VERSION 5.8 ;
BUSBITCHARS "[]" ;
DIVIDERCHAR "/" ;
UNITS
    DATABASE MICRONS 1000 ;
END UNITS

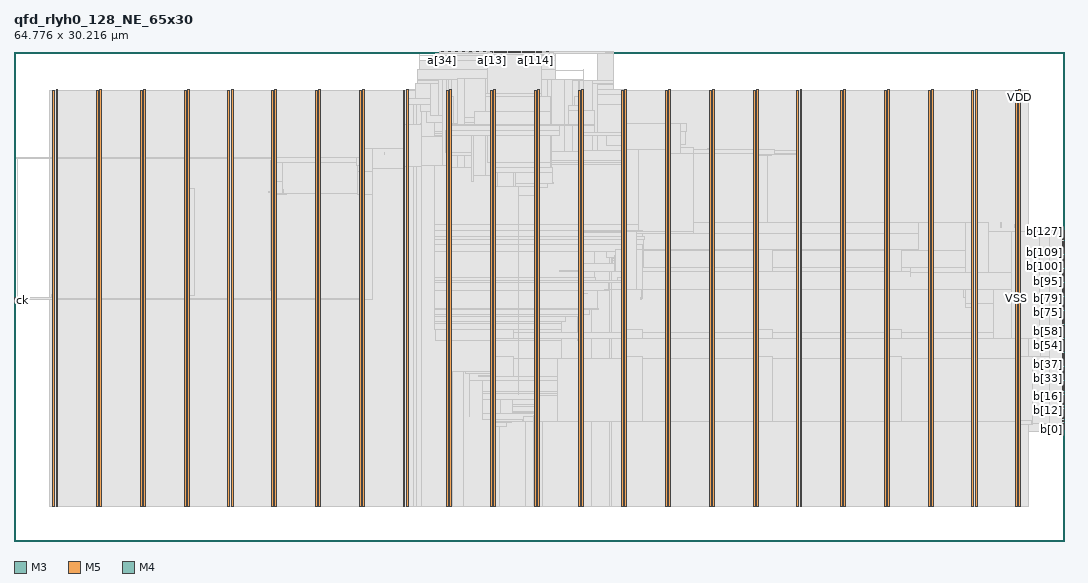
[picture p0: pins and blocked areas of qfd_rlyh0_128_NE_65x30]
MACRO qfd_rlyh0_128_NE_65x30
  FOREIGN qfd_rlyh0_128_NE_65x30 0 0 ;
  CLASS BLOCK ;
  SIZE 64.776 BY 30.216 ;
  PIN a[0]
    DIRECTION INPUT ;
    USE SIGNAL ;
    PORT
      LAYER M3 ;
        RECT  28.548 30.179 28.566 30.216 ;
    END
  END a[0]
  PIN a[100]
    DIRECTION INPUT ;
    USE SIGNAL ;
    PORT
      LAYER M3 ;
        RECT  31.14 30.179 31.158 30.216 ;
    END
  END a[100]
  PIN a[101]
    DIRECTION INPUT ;
    USE SIGNAL ;
    PORT
      LAYER M3 ;
        RECT  31.212 30.179 31.23 30.216 ;
    END
  END a[101]
  PIN a[102]
    DIRECTION INPUT ;
    USE SIGNAL ;
    PORT
      LAYER M3 ;
        RECT  31.284 30.179 31.302 30.216 ;
    END
  END a[102]
  PIN a[103]
    DIRECTION INPUT ;
    USE SIGNAL ;
    PORT
      LAYER M3 ;
        RECT  31.356 30.179 31.374 30.216 ;
    END
  END a[103]
  PIN a[104]
    DIRECTION INPUT ;
    USE SIGNAL ;
    PORT
      LAYER M3 ;
        RECT  31.428 30.179 31.446 30.216 ;
    END
  END a[104]
  PIN a[105]
    DIRECTION INPUT ;
    USE SIGNAL ;
    PORT
      LAYER M3 ;
        RECT  31.5 30.179 31.518 30.216 ;
    END
  END a[105]
  PIN a[106]
    DIRECTION INPUT ;
    USE SIGNAL ;
    PORT
      LAYER M3 ;
        RECT  31.572 30.179 31.59 30.216 ;
    END
  END a[106]
  PIN a[107]
    DIRECTION INPUT ;
    USE SIGNAL ;
    PORT
      LAYER M3 ;
        RECT  31.644 30.179 31.662 30.216 ;
    END
  END a[107]
  PIN a[108]
    DIRECTION INPUT ;
    USE SIGNAL ;
    PORT
      LAYER M3 ;
        RECT  31.716 30.179 31.734 30.216 ;
    END
  END a[108]
  PIN a[109]
    DIRECTION INPUT ;
    USE SIGNAL ;
    PORT
      LAYER M3 ;
        RECT  31.788 30.179 31.806 30.216 ;
    END
  END a[109]
  PIN a[10]
    DIRECTION INPUT ;
    USE SIGNAL ;
    PORT
      LAYER M3 ;
        RECT  29.268 30.179 29.286 30.216 ;
    END
  END a[10]
  PIN a[110]
    DIRECTION INPUT ;
    USE SIGNAL ;
    PORT
      LAYER M3 ;
        RECT  31.86 30.179 31.878 30.216 ;
    END
  END a[110]
  PIN a[111]
    DIRECTION INPUT ;
    USE SIGNAL ;
    PORT
      LAYER M3 ;
        RECT  31.932 30.179 31.95 30.216 ;
    END
  END a[111]
  PIN a[112]
    DIRECTION INPUT ;
    USE SIGNAL ;
    PORT
      LAYER M3 ;
        RECT  32.004 30.179 32.022 30.216 ;
    END
  END a[112]
  PIN a[113]
    DIRECTION INPUT ;
    USE SIGNAL ;
    PORT
      LAYER M3 ;
        RECT  32.076 30.179 32.094 30.216 ;
    END
  END a[113]
  PIN a[114]
    DIRECTION INPUT ;
    USE SIGNAL ;
    PORT
      LAYER M3 ;
        RECT  32.148 30.179 32.166 30.216 ;
    END
  END a[114]
  PIN a[115]
    DIRECTION INPUT ;
    USE SIGNAL ;
    PORT
      LAYER M3 ;
        RECT  32.22 30.179 32.238 30.216 ;
    END
  END a[115]
  PIN a[116]
    DIRECTION INPUT ;
    USE SIGNAL ;
    PORT
      LAYER M3 ;
        RECT  32.292 30.179 32.31 30.216 ;
    END
  END a[116]
  PIN a[117]
    DIRECTION INPUT ;
    USE SIGNAL ;
    PORT
      LAYER M3 ;
        RECT  32.364 30.179 32.382 30.216 ;
    END
  END a[117]
  PIN a[118]
    DIRECTION INPUT ;
    USE SIGNAL ;
    PORT
      LAYER M3 ;
        RECT  32.436 30.179 32.454 30.216 ;
    END
  END a[118]
  PIN a[119]
    DIRECTION INPUT ;
    USE SIGNAL ;
    PORT
      LAYER M3 ;
        RECT  32.508 30.179 32.526 30.216 ;
    END
  END a[119]
  PIN a[11]
    DIRECTION INPUT ;
    USE SIGNAL ;
    PORT
      LAYER M3 ;
        RECT  29.34 30.179 29.358 30.216 ;
    END
  END a[11]
  PIN a[120]
    DIRECTION INPUT ;
    USE SIGNAL ;
    PORT
      LAYER M3 ;
        RECT  32.58 30.179 32.598 30.216 ;
    END
  END a[120]
  PIN a[121]
    DIRECTION INPUT ;
    USE SIGNAL ;
    PORT
      LAYER M3 ;
        RECT  32.652 30.179 32.67 30.216 ;
    END
  END a[121]
  PIN a[122]
    DIRECTION INPUT ;
    USE SIGNAL ;
    PORT
      LAYER M3 ;
        RECT  32.724 30.179 32.742 30.216 ;
    END
  END a[122]
  PIN a[123]
    DIRECTION INPUT ;
    USE SIGNAL ;
    PORT
      LAYER M3 ;
        RECT  32.796 30.179 32.814 30.216 ;
    END
  END a[123]
  PIN a[124]
    DIRECTION INPUT ;
    USE SIGNAL ;
    PORT
      LAYER M3 ;
        RECT  32.868 30.179 32.886 30.216 ;
    END
  END a[124]
  PIN a[125]
    DIRECTION INPUT ;
    USE SIGNAL ;
    PORT
      LAYER M3 ;
        RECT  32.94 30.179 32.958 30.216 ;
    END
  END a[125]
  PIN a[126]
    DIRECTION INPUT ;
    USE SIGNAL ;
    PORT
      LAYER M3 ;
        RECT  33.012 30.179 33.03 30.216 ;
    END
  END a[126]
  PIN a[127]
    DIRECTION INPUT ;
    USE SIGNAL ;
    PORT
      LAYER M3 ;
        RECT  33.084 30.179 33.102 30.216 ;
    END
  END a[127]
  PIN a[12]
    DIRECTION INPUT ;
    USE SIGNAL ;
    PORT
      LAYER M3 ;
        RECT  29.412 30.179 29.43 30.216 ;
    END
  END a[12]
  PIN a[13]
    DIRECTION INPUT ;
    USE SIGNAL ;
    PORT
      LAYER M3 ;
        RECT  29.484 30.179 29.502 30.216 ;
    END
  END a[13]
  PIN a[14]
    DIRECTION INPUT ;
    USE SIGNAL ;
    PORT
      LAYER M3 ;
        RECT  29.556 30.179 29.574 30.216 ;
    END
  END a[14]
  PIN a[15]
    DIRECTION INPUT ;
    USE SIGNAL ;
    PORT
      LAYER M3 ;
        RECT  29.628 30.179 29.646 30.216 ;
    END
  END a[15]
  PIN a[16]
    DIRECTION INPUT ;
    USE SIGNAL ;
    PORT
      LAYER M3 ;
        RECT  29.7 30.179 29.718 30.216 ;
    END
  END a[16]
  PIN a[17]
    DIRECTION INPUT ;
    USE SIGNAL ;
    PORT
      LAYER M3 ;
        RECT  29.772 30.179 29.79 30.216 ;
    END
  END a[17]
  PIN a[18]
    DIRECTION INPUT ;
    USE SIGNAL ;
    PORT
      LAYER M3 ;
        RECT  29.844 30.179 29.862 30.216 ;
    END
  END a[18]
  PIN a[19]
    DIRECTION INPUT ;
    USE SIGNAL ;
    PORT
      LAYER M3 ;
        RECT  29.916 30.179 29.934 30.216 ;
    END
  END a[19]
  PIN a[1]
    DIRECTION INPUT ;
    USE SIGNAL ;
    PORT
      LAYER M3 ;
        RECT  28.62 30.179 28.638 30.216 ;
    END
  END a[1]
  PIN a[20]
    DIRECTION INPUT ;
    USE SIGNAL ;
    PORT
      LAYER M3 ;
        RECT  29.988 30.179 30.006 30.216 ;
    END
  END a[20]
  PIN a[21]
    DIRECTION INPUT ;
    USE SIGNAL ;
    PORT
      LAYER M3 ;
        RECT  30.06 30.179 30.078 30.216 ;
    END
  END a[21]
  PIN a[22]
    DIRECTION INPUT ;
    USE SIGNAL ;
    PORT
      LAYER M3 ;
        RECT  30.132 30.179 30.15 30.216 ;
    END
  END a[22]
  PIN a[23]
    DIRECTION INPUT ;
    USE SIGNAL ;
    PORT
      LAYER M3 ;
        RECT  30.204 30.179 30.222 30.216 ;
    END
  END a[23]
  PIN a[24]
    DIRECTION INPUT ;
    USE SIGNAL ;
    PORT
      LAYER M3 ;
        RECT  30.276 30.179 30.294 30.216 ;
    END
  END a[24]
  PIN a[25]
    DIRECTION INPUT ;
    USE SIGNAL ;
    PORT
      LAYER M3 ;
        RECT  30.348 30.179 30.366 30.216 ;
    END
  END a[25]
  PIN a[26]
    DIRECTION INPUT ;
    USE SIGNAL ;
    PORT
      LAYER M3 ;
        RECT  30.42 30.179 30.438 30.216 ;
    END
  END a[26]
  PIN a[27]
    DIRECTION INPUT ;
    USE SIGNAL ;
    PORT
      LAYER M3 ;
        RECT  30.492 30.179 30.51 30.216 ;
    END
  END a[27]
  PIN a[28]
    DIRECTION INPUT ;
    USE SIGNAL ;
    PORT
      LAYER M3 ;
        RECT  30.564 30.179 30.582 30.216 ;
    END
  END a[28]
  PIN a[29]
    DIRECTION INPUT ;
    USE SIGNAL ;
    PORT
      LAYER M3 ;
        RECT  30.636 30.179 30.654 30.216 ;
    END
  END a[29]
  PIN a[2]
    DIRECTION INPUT ;
    USE SIGNAL ;
    PORT
      LAYER M3 ;
        RECT  28.692 30.179 28.71 30.216 ;
    END
  END a[2]
  PIN a[30]
    DIRECTION INPUT ;
    USE SIGNAL ;
    PORT
      LAYER M3 ;
        RECT  30.708 30.179 30.726 30.216 ;
    END
  END a[30]
  PIN a[31]
    DIRECTION INPUT ;
    USE SIGNAL ;
    PORT
      LAYER M3 ;
        RECT  30.78 30.179 30.798 30.216 ;
    END
  END a[31]
  PIN a[32]
    DIRECTION INPUT ;
    USE SIGNAL ;
    PORT
      LAYER M3 ;
        RECT  26.244 30.179 26.262 30.216 ;
    END
  END a[32]
  PIN a[33]
    DIRECTION INPUT ;
    USE SIGNAL ;
    PORT
      LAYER M3 ;
        RECT  26.316 30.179 26.334 30.216 ;
    END
  END a[33]
  PIN a[34]
    DIRECTION INPUT ;
    USE SIGNAL ;
    PORT
      LAYER M3 ;
        RECT  26.388 30.179 26.406 30.216 ;
    END
  END a[34]
  PIN a[35]
    DIRECTION INPUT ;
    USE SIGNAL ;
    PORT
      LAYER M3 ;
        RECT  26.46 30.179 26.478 30.216 ;
    END
  END a[35]
  PIN a[36]
    DIRECTION INPUT ;
    USE SIGNAL ;
    PORT
      LAYER M3 ;
        RECT  26.532 30.179 26.55 30.216 ;
    END
  END a[36]
  PIN a[37]
    DIRECTION INPUT ;
    USE SIGNAL ;
    PORT
      LAYER M3 ;
        RECT  26.604 30.179 26.622 30.216 ;
    END
  END a[37]
  PIN a[38]
    DIRECTION INPUT ;
    USE SIGNAL ;
    PORT
      LAYER M3 ;
        RECT  26.676 30.179 26.694 30.216 ;
    END
  END a[38]
  PIN a[39]
    DIRECTION INPUT ;
    USE SIGNAL ;
    PORT
      LAYER M3 ;
        RECT  26.748 30.179 26.766 30.216 ;
    END
  END a[39]
  PIN a[3]
    DIRECTION INPUT ;
    USE SIGNAL ;
    PORT
      LAYER M3 ;
        RECT  28.764 30.179 28.782 30.216 ;
    END
  END a[3]
  PIN a[40]
    DIRECTION INPUT ;
    USE SIGNAL ;
    PORT
      LAYER M3 ;
        RECT  26.82 30.179 26.838 30.216 ;
    END
  END a[40]
  PIN a[41]
    DIRECTION INPUT ;
    USE SIGNAL ;
    PORT
      LAYER M3 ;
        RECT  26.892 30.179 26.91 30.216 ;
    END
  END a[41]
  PIN a[42]
    DIRECTION INPUT ;
    USE SIGNAL ;
    PORT
      LAYER M3 ;
        RECT  26.964 30.179 26.982 30.216 ;
    END
  END a[42]
  PIN a[43]
    DIRECTION INPUT ;
    USE SIGNAL ;
    PORT
      LAYER M3 ;
        RECT  27.036 30.179 27.054 30.216 ;
    END
  END a[43]
  PIN a[44]
    DIRECTION INPUT ;
    USE SIGNAL ;
    PORT
      LAYER M3 ;
        RECT  27.108 30.179 27.126 30.216 ;
    END
  END a[44]
  PIN a[45]
    DIRECTION INPUT ;
    USE SIGNAL ;
    PORT
      LAYER M3 ;
        RECT  27.18 30.179 27.198 30.216 ;
    END
  END a[45]
  PIN a[46]
    DIRECTION INPUT ;
    USE SIGNAL ;
    PORT
      LAYER M3 ;
        RECT  27.252 30.179 27.27 30.216 ;
    END
  END a[46]
  PIN a[47]
    DIRECTION INPUT ;
    USE SIGNAL ;
    PORT
      LAYER M3 ;
        RECT  27.324 30.179 27.342 30.216 ;
    END
  END a[47]
  PIN a[48]
    DIRECTION INPUT ;
    USE SIGNAL ;
    PORT
      LAYER M3 ;
        RECT  27.396 30.179 27.414 30.216 ;
    END
  END a[48]
  PIN a[49]
    DIRECTION INPUT ;
    USE SIGNAL ;
    PORT
      LAYER M3 ;
        RECT  27.468 30.179 27.486 30.216 ;
    END
  END a[49]
  PIN a[4]
    DIRECTION INPUT ;
    USE SIGNAL ;
    PORT
      LAYER M3 ;
        RECT  28.836 30.179 28.854 30.216 ;
    END
  END a[4]
  PIN a[50]
    DIRECTION INPUT ;
    USE SIGNAL ;
    PORT
      LAYER M3 ;
        RECT  27.54 30.179 27.558 30.216 ;
    END
  END a[50]
  PIN a[51]
    DIRECTION INPUT ;
    USE SIGNAL ;
    PORT
      LAYER M3 ;
        RECT  27.612 30.179 27.63 30.216 ;
    END
  END a[51]
  PIN a[52]
    DIRECTION INPUT ;
    USE SIGNAL ;
    PORT
      LAYER M3 ;
        RECT  27.684 30.179 27.702 30.216 ;
    END
  END a[52]
  PIN a[53]
    DIRECTION INPUT ;
    USE SIGNAL ;
    PORT
      LAYER M3 ;
        RECT  27.756 30.179 27.774 30.216 ;
    END
  END a[53]
  PIN a[54]
    DIRECTION INPUT ;
    USE SIGNAL ;
    PORT
      LAYER M3 ;
        RECT  27.828 30.179 27.846 30.216 ;
    END
  END a[54]
  PIN a[55]
    DIRECTION INPUT ;
    USE SIGNAL ;
    PORT
      LAYER M3 ;
        RECT  27.9 30.179 27.918 30.216 ;
    END
  END a[55]
  PIN a[56]
    DIRECTION INPUT ;
    USE SIGNAL ;
    PORT
      LAYER M3 ;
        RECT  27.972 30.179 27.99 30.216 ;
    END
  END a[56]
  PIN a[57]
    DIRECTION INPUT ;
    USE SIGNAL ;
    PORT
      LAYER M3 ;
        RECT  28.044 30.179 28.062 30.216 ;
    END
  END a[57]
  PIN a[58]
    DIRECTION INPUT ;
    USE SIGNAL ;
    PORT
      LAYER M3 ;
        RECT  28.116 30.179 28.134 30.216 ;
    END
  END a[58]
  PIN a[59]
    DIRECTION INPUT ;
    USE SIGNAL ;
    PORT
      LAYER M3 ;
        RECT  28.188 30.179 28.206 30.216 ;
    END
  END a[59]
  PIN a[5]
    DIRECTION INPUT ;
    USE SIGNAL ;
    PORT
      LAYER M3 ;
        RECT  28.908 30.179 28.926 30.216 ;
    END
  END a[5]
  PIN a[60]
    DIRECTION INPUT ;
    USE SIGNAL ;
    PORT
      LAYER M3 ;
        RECT  28.26 30.179 28.278 30.216 ;
    END
  END a[60]
  PIN a[61]
    DIRECTION INPUT ;
    USE SIGNAL ;
    PORT
      LAYER M3 ;
        RECT  28.332 30.179 28.35 30.216 ;
    END
  END a[61]
  PIN a[62]
    DIRECTION INPUT ;
    USE SIGNAL ;
    PORT
      LAYER M3 ;
        RECT  28.404 30.179 28.422 30.216 ;
    END
  END a[62]
  PIN a[63]
    DIRECTION INPUT ;
    USE SIGNAL ;
    PORT
      LAYER M3 ;
        RECT  28.476 30.179 28.494 30.216 ;
    END
  END a[63]
  PIN a[64]
    DIRECTION INPUT ;
    USE SIGNAL ;
    PORT
      LAYER M5 ;
        RECT  29.52 30.132 29.544 30.216 ;
    END
  END a[64]
  PIN a[65]
    DIRECTION INPUT ;
    USE SIGNAL ;
    PORT
      LAYER M5 ;
        RECT  29.616 30.132 29.64 30.216 ;
    END
  END a[65]
  PIN a[66]
    DIRECTION INPUT ;
    USE SIGNAL ;
    PORT
      LAYER M5 ;
        RECT  29.712 30.132 29.736 30.216 ;
    END
  END a[66]
  PIN a[67]
    DIRECTION INPUT ;
    USE SIGNAL ;
    PORT
      LAYER M5 ;
        RECT  29.808 30.132 29.832 30.216 ;
    END
  END a[67]
  PIN a[68]
    DIRECTION INPUT ;
    USE SIGNAL ;
    PORT
      LAYER M5 ;
        RECT  29.904 30.132 29.928 30.216 ;
    END
  END a[68]
  PIN a[69]
    DIRECTION INPUT ;
    USE SIGNAL ;
    PORT
      LAYER M5 ;
        RECT  30 30.132 30.024 30.216 ;
    END
  END a[69]
  PIN a[6]
    DIRECTION INPUT ;
    USE SIGNAL ;
    PORT
      LAYER M3 ;
        RECT  28.98 30.179 28.998 30.216 ;
    END
  END a[6]
  PIN a[70]
    DIRECTION INPUT ;
    USE SIGNAL ;
    PORT
      LAYER M5 ;
        RECT  30.096 30.132 30.12 30.216 ;
    END
  END a[70]
  PIN a[71]
    DIRECTION INPUT ;
    USE SIGNAL ;
    PORT
      LAYER M5 ;
        RECT  30.192 30.132 30.216 30.216 ;
    END
  END a[71]
  PIN a[72]
    DIRECTION INPUT ;
    USE SIGNAL ;
    PORT
      LAYER M5 ;
        RECT  30.288 30.132 30.312 30.216 ;
    END
  END a[72]
  PIN a[73]
    DIRECTION INPUT ;
    USE SIGNAL ;
    PORT
      LAYER M5 ;
        RECT  30.384 30.132 30.408 30.216 ;
    END
  END a[73]
  PIN a[74]
    DIRECTION INPUT ;
    USE SIGNAL ;
    PORT
      LAYER M5 ;
        RECT  30.48 30.132 30.504 30.216 ;
    END
  END a[74]
  PIN a[75]
    DIRECTION INPUT ;
    USE SIGNAL ;
    PORT
      LAYER M5 ;
        RECT  30.576 30.132 30.6 30.216 ;
    END
  END a[75]
  PIN a[76]
    DIRECTION INPUT ;
    USE SIGNAL ;
    PORT
      LAYER M5 ;
        RECT  30.672 30.132 30.696 30.216 ;
    END
  END a[76]
  PIN a[77]
    DIRECTION INPUT ;
    USE SIGNAL ;
    PORT
      LAYER M5 ;
        RECT  30.768 30.132 30.792 30.216 ;
    END
  END a[77]
  PIN a[78]
    DIRECTION INPUT ;
    USE SIGNAL ;
    PORT
      LAYER M5 ;
        RECT  30.864 30.132 30.888 30.216 ;
    END
  END a[78]
  PIN a[79]
    DIRECTION INPUT ;
    USE SIGNAL ;
    PORT
      LAYER M5 ;
        RECT  30.96 30.132 30.984 30.216 ;
    END
  END a[79]
  PIN a[7]
    DIRECTION INPUT ;
    USE SIGNAL ;
    PORT
      LAYER M3 ;
        RECT  29.052 30.179 29.07 30.216 ;
    END
  END a[7]
  PIN a[80]
    DIRECTION INPUT ;
    USE SIGNAL ;
    PORT
      LAYER M5 ;
        RECT  31.056 30.132 31.08 30.216 ;
    END
  END a[80]
  PIN a[81]
    DIRECTION INPUT ;
    USE SIGNAL ;
    PORT
      LAYER M5 ;
        RECT  31.152 30.132 31.176 30.216 ;
    END
  END a[81]
  PIN a[82]
    DIRECTION INPUT ;
    USE SIGNAL ;
    PORT
      LAYER M5 ;
        RECT  31.248 30.132 31.272 30.216 ;
    END
  END a[82]
  PIN a[83]
    DIRECTION INPUT ;
    USE SIGNAL ;
    PORT
      LAYER M5 ;
        RECT  31.344 30.132 31.368 30.216 ;
    END
  END a[83]
  PIN a[84]
    DIRECTION INPUT ;
    USE SIGNAL ;
    PORT
      LAYER M5 ;
        RECT  31.44 30.132 31.464 30.216 ;
    END
  END a[84]
  PIN a[85]
    DIRECTION INPUT ;
    USE SIGNAL ;
    PORT
      LAYER M5 ;
        RECT  31.536 30.132 31.56 30.216 ;
    END
  END a[85]
  PIN a[86]
    DIRECTION INPUT ;
    USE SIGNAL ;
    PORT
      LAYER M5 ;
        RECT  31.632 30.132 31.656 30.216 ;
    END
  END a[86]
  PIN a[87]
    DIRECTION INPUT ;
    USE SIGNAL ;
    PORT
      LAYER M5 ;
        RECT  31.728 30.132 31.752 30.216 ;
    END
  END a[87]
  PIN a[88]
    DIRECTION INPUT ;
    USE SIGNAL ;
    PORT
      LAYER M5 ;
        RECT  31.824 30.132 31.848 30.216 ;
    END
  END a[88]
  PIN a[89]
    DIRECTION INPUT ;
    USE SIGNAL ;
    PORT
      LAYER M5 ;
        RECT  31.92 30.132 31.944 30.216 ;
    END
  END a[89]
  PIN a[8]
    DIRECTION INPUT ;
    USE SIGNAL ;
    PORT
      LAYER M3 ;
        RECT  29.124 30.179 29.142 30.216 ;
    END
  END a[8]
  PIN a[90]
    DIRECTION INPUT ;
    USE SIGNAL ;
    PORT
      LAYER M5 ;
        RECT  32.016 30.132 32.04 30.216 ;
    END
  END a[90]
  PIN a[91]
    DIRECTION INPUT ;
    USE SIGNAL ;
    PORT
      LAYER M5 ;
        RECT  32.112 30.132 32.136 30.216 ;
    END
  END a[91]
  PIN a[92]
    DIRECTION INPUT ;
    USE SIGNAL ;
    PORT
      LAYER M5 ;
        RECT  32.208 30.132 32.232 30.216 ;
    END
  END a[92]
  PIN a[93]
    DIRECTION INPUT ;
    USE SIGNAL ;
    PORT
      LAYER M5 ;
        RECT  32.304 30.132 32.328 30.216 ;
    END
  END a[93]
  PIN a[94]
    DIRECTION INPUT ;
    USE SIGNAL ;
    PORT
      LAYER M5 ;
        RECT  32.4 30.132 32.424 30.216 ;
    END
  END a[94]
  PIN a[95]
    DIRECTION INPUT ;
    USE SIGNAL ;
    PORT
      LAYER M5 ;
        RECT  32.496 30.132 32.52 30.216 ;
    END
  END a[95]
  PIN a[96]
    DIRECTION INPUT ;
    USE SIGNAL ;
    PORT
      LAYER M3 ;
        RECT  30.852 30.179 30.87 30.216 ;
    END
  END a[96]
  PIN a[97]
    DIRECTION INPUT ;
    USE SIGNAL ;
    PORT
      LAYER M3 ;
        RECT  30.924 30.179 30.942 30.216 ;
    END
  END a[97]
  PIN a[98]
    DIRECTION INPUT ;
    USE SIGNAL ;
    PORT
      LAYER M3 ;
        RECT  30.996 30.179 31.014 30.216 ;
    END
  END a[98]
  PIN a[99]
    DIRECTION INPUT ;
    USE SIGNAL ;
    PORT
      LAYER M3 ;
        RECT  31.068 30.179 31.086 30.216 ;
    END
  END a[99]
  PIN a[9]
    DIRECTION INPUT ;
    USE SIGNAL ;
    PORT
      LAYER M3 ;
        RECT  29.196 30.179 29.214 30.216 ;
    END
  END a[9]
  PIN b[0]
    DIRECTION OUTPUT ;
    USE SIGNAL ;
    PORT
      LAYER M4 ;
        RECT  64.692 6.864 64.776 6.888 ;
    END
  END b[0]
  PIN b[100]
    DIRECTION OUTPUT ;
    USE SIGNAL ;
    PORT
      LAYER M4 ;
        RECT  64.692 16.464 64.776 16.488 ;
    END
  END b[100]
  PIN b[101]
    DIRECTION OUTPUT ;
    USE SIGNAL ;
    PORT
      LAYER M4 ;
        RECT  64.692 16.56 64.776 16.584 ;
    END
  END b[101]
  PIN b[102]
    DIRECTION OUTPUT ;
    USE SIGNAL ;
    PORT
      LAYER M4 ;
        RECT  64.692 16.656 64.776 16.68 ;
    END
  END b[102]
  PIN b[103]
    DIRECTION OUTPUT ;
    USE SIGNAL ;
    PORT
      LAYER M4 ;
        RECT  64.692 16.752 64.776 16.776 ;
    END
  END b[103]
  PIN b[104]
    DIRECTION OUTPUT ;
    USE SIGNAL ;
    PORT
      LAYER M4 ;
        RECT  64.692 16.848 64.776 16.872 ;
    END
  END b[104]
  PIN b[105]
    DIRECTION OUTPUT ;
    USE SIGNAL ;
    PORT
      LAYER M4 ;
        RECT  64.692 16.944 64.776 16.968 ;
    END
  END b[105]
  PIN b[106]
    DIRECTION OUTPUT ;
    USE SIGNAL ;
    PORT
      LAYER M4 ;
        RECT  64.692 17.04 64.776 17.064 ;
    END
  END b[106]
  PIN b[107]
    DIRECTION OUTPUT ;
    USE SIGNAL ;
    PORT
      LAYER M4 ;
        RECT  64.692 17.136 64.776 17.16 ;
    END
  END b[107]
  PIN b[108]
    DIRECTION OUTPUT ;
    USE SIGNAL ;
    PORT
      LAYER M4 ;
        RECT  64.692 17.232 64.776 17.256 ;
    END
  END b[108]
  PIN b[109]
    DIRECTION OUTPUT ;
    USE SIGNAL ;
    PORT
      LAYER M4 ;
        RECT  64.692 17.328 64.776 17.352 ;
    END
  END b[109]
  PIN b[10]
    DIRECTION OUTPUT ;
    USE SIGNAL ;
    PORT
      LAYER M4 ;
        RECT  64.692 7.824 64.776 7.848 ;
    END
  END b[10]
  PIN b[110]
    DIRECTION OUTPUT ;
    USE SIGNAL ;
    PORT
      LAYER M4 ;
        RECT  64.692 17.424 64.776 17.448 ;
    END
  END b[110]
  PIN b[111]
    DIRECTION OUTPUT ;
    USE SIGNAL ;
    PORT
      LAYER M4 ;
        RECT  64.692 17.52 64.776 17.544 ;
    END
  END b[111]
  PIN b[112]
    DIRECTION OUTPUT ;
    USE SIGNAL ;
    PORT
      LAYER M4 ;
        RECT  64.692 17.616 64.776 17.64 ;
    END
  END b[112]
  PIN b[113]
    DIRECTION OUTPUT ;
    USE SIGNAL ;
    PORT
      LAYER M4 ;
        RECT  64.692 17.712 64.776 17.736 ;
    END
  END b[113]
  PIN b[114]
    DIRECTION OUTPUT ;
    USE SIGNAL ;
    PORT
      LAYER M4 ;
        RECT  64.692 17.808 64.776 17.832 ;
    END
  END b[114]
  PIN b[115]
    DIRECTION OUTPUT ;
    USE SIGNAL ;
    PORT
      LAYER M4 ;
        RECT  64.692 17.904 64.776 17.928 ;
    END
  END b[115]
  PIN b[116]
    DIRECTION OUTPUT ;
    USE SIGNAL ;
    PORT
      LAYER M4 ;
        RECT  64.692 18 64.776 18.024 ;
    END
  END b[116]
  PIN b[117]
    DIRECTION OUTPUT ;
    USE SIGNAL ;
    PORT
      LAYER M4 ;
        RECT  64.692 18.096 64.776 18.12 ;
    END
  END b[117]
  PIN b[118]
    DIRECTION OUTPUT ;
    USE SIGNAL ;
    PORT
      LAYER M4 ;
        RECT  64.692 18.192 64.776 18.216 ;
    END
  END b[118]
  PIN b[119]
    DIRECTION OUTPUT ;
    USE SIGNAL ;
    PORT
      LAYER M4 ;
        RECT  64.692 18.288 64.776 18.312 ;
    END
  END b[119]
  PIN b[11]
    DIRECTION OUTPUT ;
    USE SIGNAL ;
    PORT
      LAYER M4 ;
        RECT  64.692 7.92 64.776 7.944 ;
    END
  END b[11]
  PIN b[120]
    DIRECTION OUTPUT ;
    USE SIGNAL ;
    PORT
      LAYER M4 ;
        RECT  64.692 18.384 64.776 18.408 ;
    END
  END b[120]
  PIN b[121]
    DIRECTION OUTPUT ;
    USE SIGNAL ;
    PORT
      LAYER M4 ;
        RECT  64.692 18.48 64.776 18.504 ;
    END
  END b[121]
  PIN b[122]
    DIRECTION OUTPUT ;
    USE SIGNAL ;
    PORT
      LAYER M4 ;
        RECT  64.692 18.576 64.776 18.6 ;
    END
  END b[122]
  PIN b[123]
    DIRECTION OUTPUT ;
    USE SIGNAL ;
    PORT
      LAYER M4 ;
        RECT  64.692 18.672 64.776 18.696 ;
    END
  END b[123]
  PIN b[124]
    DIRECTION OUTPUT ;
    USE SIGNAL ;
    PORT
      LAYER M4 ;
        RECT  64.692 18.768 64.776 18.792 ;
    END
  END b[124]
  PIN b[125]
    DIRECTION OUTPUT ;
    USE SIGNAL ;
    PORT
      LAYER M4 ;
        RECT  64.692 18.864 64.776 18.888 ;
    END
  END b[125]
  PIN b[126]
    DIRECTION OUTPUT ;
    USE SIGNAL ;
    PORT
      LAYER M4 ;
        RECT  64.692 18.96 64.776 18.984 ;
    END
  END b[126]
  PIN b[127]
    DIRECTION OUTPUT ;
    USE SIGNAL ;
    PORT
      LAYER M4 ;
        RECT  64.692 19.056 64.776 19.08 ;
    END
  END b[127]
  PIN b[12]
    DIRECTION OUTPUT ;
    USE SIGNAL ;
    PORT
      LAYER M4 ;
        RECT  64.692 8.016 64.776 8.04 ;
    END
  END b[12]
  PIN b[13]
    DIRECTION OUTPUT ;
    USE SIGNAL ;
    PORT
      LAYER M4 ;
        RECT  64.692 8.112 64.776 8.136 ;
    END
  END b[13]
  PIN b[14]
    DIRECTION OUTPUT ;
    USE SIGNAL ;
    PORT
      LAYER M4 ;
        RECT  64.692 8.208 64.776 8.232 ;
    END
  END b[14]
  PIN b[15]
    DIRECTION OUTPUT ;
    USE SIGNAL ;
    PORT
      LAYER M4 ;
        RECT  64.692 8.304 64.776 8.328 ;
    END
  END b[15]
  PIN b[16]
    DIRECTION OUTPUT ;
    USE SIGNAL ;
    PORT
      LAYER M4 ;
        RECT  64.692 8.4 64.776 8.424 ;
    END
  END b[16]
  PIN b[17]
    DIRECTION OUTPUT ;
    USE SIGNAL ;
    PORT
      LAYER M4 ;
        RECT  64.692 8.496 64.776 8.52 ;
    END
  END b[17]
  PIN b[18]
    DIRECTION OUTPUT ;
    USE SIGNAL ;
    PORT
      LAYER M4 ;
        RECT  64.692 8.592 64.776 8.616 ;
    END
  END b[18]
  PIN b[19]
    DIRECTION OUTPUT ;
    USE SIGNAL ;
    PORT
      LAYER M4 ;
        RECT  64.692 8.688 64.776 8.712 ;
    END
  END b[19]
  PIN b[1]
    DIRECTION OUTPUT ;
    USE SIGNAL ;
    PORT
      LAYER M4 ;
        RECT  64.692 6.96 64.776 6.984 ;
    END
  END b[1]
  PIN b[20]
    DIRECTION OUTPUT ;
    USE SIGNAL ;
    PORT
      LAYER M4 ;
        RECT  64.692 8.784 64.776 8.808 ;
    END
  END b[20]
  PIN b[21]
    DIRECTION OUTPUT ;
    USE SIGNAL ;
    PORT
      LAYER M4 ;
        RECT  64.692 8.88 64.776 8.904 ;
    END
  END b[21]
  PIN b[22]
    DIRECTION OUTPUT ;
    USE SIGNAL ;
    PORT
      LAYER M4 ;
        RECT  64.692 8.976 64.776 9 ;
    END
  END b[22]
  PIN b[23]
    DIRECTION OUTPUT ;
    USE SIGNAL ;
    PORT
      LAYER M4 ;
        RECT  64.692 9.072 64.776 9.096 ;
    END
  END b[23]
  PIN b[24]
    DIRECTION OUTPUT ;
    USE SIGNAL ;
    PORT
      LAYER M4 ;
        RECT  64.692 9.168 64.776 9.192 ;
    END
  END b[24]
  PIN b[25]
    DIRECTION OUTPUT ;
    USE SIGNAL ;
    PORT
      LAYER M4 ;
        RECT  64.692 9.264 64.776 9.288 ;
    END
  END b[25]
  PIN b[26]
    DIRECTION OUTPUT ;
    USE SIGNAL ;
    PORT
      LAYER M4 ;
        RECT  64.692 9.36 64.776 9.384 ;
    END
  END b[26]
  PIN b[27]
    DIRECTION OUTPUT ;
    USE SIGNAL ;
    PORT
      LAYER M4 ;
        RECT  64.692 9.456 64.776 9.48 ;
    END
  END b[27]
  PIN b[28]
    DIRECTION OUTPUT ;
    USE SIGNAL ;
    PORT
      LAYER M4 ;
        RECT  64.692 9.552 64.776 9.576 ;
    END
  END b[28]
  PIN b[29]
    DIRECTION OUTPUT ;
    USE SIGNAL ;
    PORT
      LAYER M4 ;
        RECT  64.692 9.648 64.776 9.672 ;
    END
  END b[29]
  PIN b[2]
    DIRECTION OUTPUT ;
    USE SIGNAL ;
    PORT
      LAYER M4 ;
        RECT  64.692 7.056 64.776 7.08 ;
    END
  END b[2]
  PIN b[30]
    DIRECTION OUTPUT ;
    USE SIGNAL ;
    PORT
      LAYER M4 ;
        RECT  64.692 9.744 64.776 9.768 ;
    END
  END b[30]
  PIN b[31]
    DIRECTION OUTPUT ;
    USE SIGNAL ;
    PORT
      LAYER M4 ;
        RECT  64.692 9.84 64.776 9.864 ;
    END
  END b[31]
  PIN b[32]
    DIRECTION OUTPUT ;
    USE SIGNAL ;
    PORT
      LAYER M4 ;
        RECT  64.692 9.936 64.776 9.96 ;
    END
  END b[32]
  PIN b[33]
    DIRECTION OUTPUT ;
    USE SIGNAL ;
    PORT
      LAYER M4 ;
        RECT  64.692 10.032 64.776 10.056 ;
    END
  END b[33]
  PIN b[34]
    DIRECTION OUTPUT ;
    USE SIGNAL ;
    PORT
      LAYER M4 ;
        RECT  64.692 10.128 64.776 10.152 ;
    END
  END b[34]
  PIN b[35]
    DIRECTION OUTPUT ;
    USE SIGNAL ;
    PORT
      LAYER M4 ;
        RECT  64.692 10.224 64.776 10.248 ;
    END
  END b[35]
  PIN b[36]
    DIRECTION OUTPUT ;
    USE SIGNAL ;
    PORT
      LAYER M4 ;
        RECT  64.692 10.32 64.776 10.344 ;
    END
  END b[36]
  PIN b[37]
    DIRECTION OUTPUT ;
    USE SIGNAL ;
    PORT
      LAYER M4 ;
        RECT  64.692 10.416 64.776 10.44 ;
    END
  END b[37]
  PIN b[38]
    DIRECTION OUTPUT ;
    USE SIGNAL ;
    PORT
      LAYER M4 ;
        RECT  64.692 10.512 64.776 10.536 ;
    END
  END b[38]
  PIN b[39]
    DIRECTION OUTPUT ;
    USE SIGNAL ;
    PORT
      LAYER M4 ;
        RECT  64.692 10.608 64.776 10.632 ;
    END
  END b[39]
  PIN b[3]
    DIRECTION OUTPUT ;
    USE SIGNAL ;
    PORT
      LAYER M4 ;
        RECT  64.692 7.152 64.776 7.176 ;
    END
  END b[3]
  PIN b[40]
    DIRECTION OUTPUT ;
    USE SIGNAL ;
    PORT
      LAYER M4 ;
        RECT  64.692 10.704 64.776 10.728 ;
    END
  END b[40]
  PIN b[41]
    DIRECTION OUTPUT ;
    USE SIGNAL ;
    PORT
      LAYER M4 ;
        RECT  64.692 10.8 64.776 10.824 ;
    END
  END b[41]
  PIN b[42]
    DIRECTION OUTPUT ;
    USE SIGNAL ;
    PORT
      LAYER M4 ;
        RECT  64.692 10.896 64.776 10.92 ;
    END
  END b[42]
  PIN b[43]
    DIRECTION OUTPUT ;
    USE SIGNAL ;
    PORT
      LAYER M4 ;
        RECT  64.692 10.992 64.776 11.016 ;
    END
  END b[43]
  PIN b[44]
    DIRECTION OUTPUT ;
    USE SIGNAL ;
    PORT
      LAYER M4 ;
        RECT  64.692 11.088 64.776 11.112 ;
    END
  END b[44]
  PIN b[45]
    DIRECTION OUTPUT ;
    USE SIGNAL ;
    PORT
      LAYER M4 ;
        RECT  64.692 11.184 64.776 11.208 ;
    END
  END b[45]
  PIN b[46]
    DIRECTION OUTPUT ;
    USE SIGNAL ;
    PORT
      LAYER M4 ;
        RECT  64.692 11.28 64.776 11.304 ;
    END
  END b[46]
  PIN b[47]
    DIRECTION OUTPUT ;
    USE SIGNAL ;
    PORT
      LAYER M4 ;
        RECT  64.692 11.376 64.776 11.4 ;
    END
  END b[47]
  PIN b[48]
    DIRECTION OUTPUT ;
    USE SIGNAL ;
    PORT
      LAYER M4 ;
        RECT  64.692 11.472 64.776 11.496 ;
    END
  END b[48]
  PIN b[49]
    DIRECTION OUTPUT ;
    USE SIGNAL ;
    PORT
      LAYER M4 ;
        RECT  64.692 11.568 64.776 11.592 ;
    END
  END b[49]
  PIN b[4]
    DIRECTION OUTPUT ;
    USE SIGNAL ;
    PORT
      LAYER M4 ;
        RECT  64.692 7.248 64.776 7.272 ;
    END
  END b[4]
  PIN b[50]
    DIRECTION OUTPUT ;
    USE SIGNAL ;
    PORT
      LAYER M4 ;
        RECT  64.692 11.664 64.776 11.688 ;
    END
  END b[50]
  PIN b[51]
    DIRECTION OUTPUT ;
    USE SIGNAL ;
    PORT
      LAYER M4 ;
        RECT  64.692 11.76 64.776 11.784 ;
    END
  END b[51]
  PIN b[52]
    DIRECTION OUTPUT ;
    USE SIGNAL ;
    PORT
      LAYER M4 ;
        RECT  64.692 11.856 64.776 11.88 ;
    END
  END b[52]
  PIN b[53]
    DIRECTION OUTPUT ;
    USE SIGNAL ;
    PORT
      LAYER M4 ;
        RECT  64.692 11.952 64.776 11.976 ;
    END
  END b[53]
  PIN b[54]
    DIRECTION OUTPUT ;
    USE SIGNAL ;
    PORT
      LAYER M4 ;
        RECT  64.692 12.048 64.776 12.072 ;
    END
  END b[54]
  PIN b[55]
    DIRECTION OUTPUT ;
    USE SIGNAL ;
    PORT
      LAYER M4 ;
        RECT  64.692 12.144 64.776 12.168 ;
    END
  END b[55]
  PIN b[56]
    DIRECTION OUTPUT ;
    USE SIGNAL ;
    PORT
      LAYER M4 ;
        RECT  64.692 12.24 64.776 12.264 ;
    END
  END b[56]
  PIN b[57]
    DIRECTION OUTPUT ;
    USE SIGNAL ;
    PORT
      LAYER M4 ;
        RECT  64.692 12.336 64.776 12.36 ;
    END
  END b[57]
  PIN b[58]
    DIRECTION OUTPUT ;
    USE SIGNAL ;
    PORT
      LAYER M4 ;
        RECT  64.692 12.432 64.776 12.456 ;
    END
  END b[58]
  PIN b[59]
    DIRECTION OUTPUT ;
    USE SIGNAL ;
    PORT
      LAYER M4 ;
        RECT  64.692 12.528 64.776 12.552 ;
    END
  END b[59]
  PIN b[5]
    DIRECTION OUTPUT ;
    USE SIGNAL ;
    PORT
      LAYER M4 ;
        RECT  64.692 7.344 64.776 7.368 ;
    END
  END b[5]
  PIN b[60]
    DIRECTION OUTPUT ;
    USE SIGNAL ;
    PORT
      LAYER M4 ;
        RECT  64.692 12.624 64.776 12.648 ;
    END
  END b[60]
  PIN b[61]
    DIRECTION OUTPUT ;
    USE SIGNAL ;
    PORT
      LAYER M4 ;
        RECT  64.692 12.72 64.776 12.744 ;
    END
  END b[61]
  PIN b[62]
    DIRECTION OUTPUT ;
    USE SIGNAL ;
    PORT
      LAYER M4 ;
        RECT  64.692 12.816 64.776 12.84 ;
    END
  END b[62]
  PIN b[63]
    DIRECTION OUTPUT ;
    USE SIGNAL ;
    PORT
      LAYER M4 ;
        RECT  64.692 12.912 64.776 12.936 ;
    END
  END b[63]
  PIN b[64]
    DIRECTION OUTPUT ;
    USE SIGNAL ;
    PORT
      LAYER M4 ;
        RECT  64.692 13.008 64.776 13.032 ;
    END
  END b[64]
  PIN b[65]
    DIRECTION OUTPUT ;
    USE SIGNAL ;
    PORT
      LAYER M4 ;
        RECT  64.692 13.104 64.776 13.128 ;
    END
  END b[65]
  PIN b[66]
    DIRECTION OUTPUT ;
    USE SIGNAL ;
    PORT
      LAYER M4 ;
        RECT  64.692 13.2 64.776 13.224 ;
    END
  END b[66]
  PIN b[67]
    DIRECTION OUTPUT ;
    USE SIGNAL ;
    PORT
      LAYER M4 ;
        RECT  64.692 13.296 64.776 13.32 ;
    END
  END b[67]
  PIN b[68]
    DIRECTION OUTPUT ;
    USE SIGNAL ;
    PORT
      LAYER M4 ;
        RECT  64.692 13.392 64.776 13.416 ;
    END
  END b[68]
  PIN b[69]
    DIRECTION OUTPUT ;
    USE SIGNAL ;
    PORT
      LAYER M4 ;
        RECT  64.692 13.488 64.776 13.512 ;
    END
  END b[69]
  PIN b[6]
    DIRECTION OUTPUT ;
    USE SIGNAL ;
    PORT
      LAYER M4 ;
        RECT  64.692 7.44 64.776 7.464 ;
    END
  END b[6]
  PIN b[70]
    DIRECTION OUTPUT ;
    USE SIGNAL ;
    PORT
      LAYER M4 ;
        RECT  64.692 13.584 64.776 13.608 ;
    END
  END b[70]
  PIN b[71]
    DIRECTION OUTPUT ;
    USE SIGNAL ;
    PORT
      LAYER M4 ;
        RECT  64.692 13.68 64.776 13.704 ;
    END
  END b[71]
  PIN b[72]
    DIRECTION OUTPUT ;
    USE SIGNAL ;
    PORT
      LAYER M4 ;
        RECT  64.692 13.776 64.776 13.8 ;
    END
  END b[72]
  PIN b[73]
    DIRECTION OUTPUT ;
    USE SIGNAL ;
    PORT
      LAYER M4 ;
        RECT  64.692 13.872 64.776 13.896 ;
    END
  END b[73]
  PIN b[74]
    DIRECTION OUTPUT ;
    USE SIGNAL ;
    PORT
      LAYER M4 ;
        RECT  64.692 13.968 64.776 13.992 ;
    END
  END b[74]
  PIN b[75]
    DIRECTION OUTPUT ;
    USE SIGNAL ;
    PORT
      LAYER M4 ;
        RECT  64.692 14.064 64.776 14.088 ;
    END
  END b[75]
  PIN b[76]
    DIRECTION OUTPUT ;
    USE SIGNAL ;
    PORT
      LAYER M4 ;
        RECT  64.692 14.16 64.776 14.184 ;
    END
  END b[76]
  PIN b[77]
    DIRECTION OUTPUT ;
    USE SIGNAL ;
    PORT
      LAYER M4 ;
        RECT  64.692 14.256 64.776 14.28 ;
    END
  END b[77]
  PIN b[78]
    DIRECTION OUTPUT ;
    USE SIGNAL ;
    PORT
      LAYER M4 ;
        RECT  64.692 14.352 64.776 14.376 ;
    END
  END b[78]
  PIN b[79]
    DIRECTION OUTPUT ;
    USE SIGNAL ;
    PORT
      LAYER M4 ;
        RECT  64.692 14.448 64.776 14.472 ;
    END
  END b[79]
  PIN b[7]
    DIRECTION OUTPUT ;
    USE SIGNAL ;
    PORT
      LAYER M4 ;
        RECT  64.692 7.536 64.776 7.56 ;
    END
  END b[7]
  PIN b[80]
    DIRECTION OUTPUT ;
    USE SIGNAL ;
    PORT
      LAYER M4 ;
        RECT  64.692 14.544 64.776 14.568 ;
    END
  END b[80]
  PIN b[81]
    DIRECTION OUTPUT ;
    USE SIGNAL ;
    PORT
      LAYER M4 ;
        RECT  64.692 14.64 64.776 14.664 ;
    END
  END b[81]
  PIN b[82]
    DIRECTION OUTPUT ;
    USE SIGNAL ;
    PORT
      LAYER M4 ;
        RECT  64.692 14.736 64.776 14.76 ;
    END
  END b[82]
  PIN b[83]
    DIRECTION OUTPUT ;
    USE SIGNAL ;
    PORT
      LAYER M4 ;
        RECT  64.692 14.832 64.776 14.856 ;
    END
  END b[83]
  PIN b[84]
    DIRECTION OUTPUT ;
    USE SIGNAL ;
    PORT
      LAYER M4 ;
        RECT  64.692 14.928 64.776 14.952 ;
    END
  END b[84]
  PIN b[85]
    DIRECTION OUTPUT ;
    USE SIGNAL ;
    PORT
      LAYER M4 ;
        RECT  64.692 15.024 64.776 15.048 ;
    END
  END b[85]
  PIN b[86]
    DIRECTION OUTPUT ;
    USE SIGNAL ;
    PORT
      LAYER M4 ;
        RECT  64.692 15.12 64.776 15.144 ;
    END
  END b[86]
  PIN b[87]
    DIRECTION OUTPUT ;
    USE SIGNAL ;
    PORT
      LAYER M4 ;
        RECT  64.692 15.216 64.776 15.24 ;
    END
  END b[87]
  PIN b[88]
    DIRECTION OUTPUT ;
    USE SIGNAL ;
    PORT
      LAYER M4 ;
        RECT  64.692 15.312 64.776 15.336 ;
    END
  END b[88]
  PIN b[89]
    DIRECTION OUTPUT ;
    USE SIGNAL ;
    PORT
      LAYER M4 ;
        RECT  64.692 15.408 64.776 15.432 ;
    END
  END b[89]
  PIN b[8]
    DIRECTION OUTPUT ;
    USE SIGNAL ;
    PORT
      LAYER M4 ;
        RECT  64.692 7.632 64.776 7.656 ;
    END
  END b[8]
  PIN b[90]
    DIRECTION OUTPUT ;
    USE SIGNAL ;
    PORT
      LAYER M4 ;
        RECT  64.692 15.504 64.776 15.528 ;
    END
  END b[90]
  PIN b[91]
    DIRECTION OUTPUT ;
    USE SIGNAL ;
    PORT
      LAYER M4 ;
        RECT  64.692 15.6 64.776 15.624 ;
    END
  END b[91]
  PIN b[92]
    DIRECTION OUTPUT ;
    USE SIGNAL ;
    PORT
      LAYER M4 ;
        RECT  64.692 15.696 64.776 15.72 ;
    END
  END b[92]
  PIN b[93]
    DIRECTION OUTPUT ;
    USE SIGNAL ;
    PORT
      LAYER M4 ;
        RECT  64.692 15.792 64.776 15.816 ;
    END
  END b[93]
  PIN b[94]
    DIRECTION OUTPUT ;
    USE SIGNAL ;
    PORT
      LAYER M4 ;
        RECT  64.692 15.888 64.776 15.912 ;
    END
  END b[94]
  PIN b[95]
    DIRECTION OUTPUT ;
    USE SIGNAL ;
    PORT
      LAYER M4 ;
        RECT  64.692 15.984 64.776 16.008 ;
    END
  END b[95]
  PIN b[96]
    DIRECTION OUTPUT ;
    USE SIGNAL ;
    PORT
      LAYER M4 ;
        RECT  64.692 16.08 64.776 16.104 ;
    END
  END b[96]
  PIN b[97]
    DIRECTION OUTPUT ;
    USE SIGNAL ;
    PORT
      LAYER M4 ;
        RECT  64.692 16.176 64.776 16.2 ;
    END
  END b[97]
  PIN b[98]
    DIRECTION OUTPUT ;
    USE SIGNAL ;
    PORT
      LAYER M4 ;
        RECT  64.692 16.272 64.776 16.296 ;
    END
  END b[98]
  PIN b[99]
    DIRECTION OUTPUT ;
    USE SIGNAL ;
    PORT
      LAYER M4 ;
        RECT  64.692 16.368 64.776 16.392 ;
    END
  END b[99]
  PIN b[9]
    DIRECTION OUTPUT ;
    USE SIGNAL ;
    PORT
      LAYER M4 ;
        RECT  64.692 7.728 64.776 7.752 ;
    END
  END b[9]
  PIN ck
    DIRECTION INPUT ;
    USE SIGNAL ;
    PORT
      LAYER M4 ;
        RECT  0 14.832 0.084 14.856 ;
    END
  END ck
  PIN ck_o
    DIRECTION OUTPUT ;
    USE SIGNAL ;
    PORT
      LAYER M4 ;
        RECT  0 14.928 0.084 14.952 ;
    END
  END ck_o
  PIN eb
    DIRECTION OUTPUT ;
    USE SIGNAL ;
    PORT
      LAYER M4 ;
        RECT  64.692 19.152 64.776 19.176 ;
    END
  END eb
  PIN en
    DIRECTION INPUT ;
    USE SIGNAL ;
    PORT
      LAYER M4 ;
        RECT  0 15.024 0.084 15.048 ;
    END
  END en
  PIN VDD
    DIRECTION INOUT ;
    USE POWER ;
    PORT
      LAYER M5 ;
        RECT  61.992 2.151 62.112 27.833 ;
        RECT  59.292 2.151 59.412 27.833 ;
        RECT  56.592 2.151 56.712 27.833 ;
        RECT  53.892 2.151 54.012 27.833 ;
        RECT  51.192 2.151 51.312 27.833 ;
        RECT  48.492 2.151 48.612 27.833 ;
        RECT  45.792 2.151 45.912 27.833 ;
        RECT  43.092 2.151 43.212 27.833 ;
        RECT  40.392 2.151 40.512 27.833 ;
        RECT  37.692 2.151 37.812 27.833 ;
        RECT  34.992 2.151 35.112 27.833 ;
        RECT  32.292 2.151 32.412 27.833 ;
        RECT  29.592 2.151 29.712 27.833 ;
        RECT  26.892 2.151 27.012 27.833 ;
        RECT  24.192 2.151 24.312 27.833 ;
        RECT  21.492 2.151 21.612 27.833 ;
        RECT  18.792 2.151 18.912 27.833 ;
        RECT  16.092 2.151 16.212 27.833 ;
        RECT  13.392 2.151 13.512 27.833 ;
        RECT  10.692 2.151 10.812 27.833 ;
        RECT  7.992 2.151 8.112 27.833 ;
        RECT  5.292 2.151 5.412 27.833 ;
        RECT  2.592 2.151 2.712 27.833 ;
    END
  END VDD
  PIN VSS
    DIRECTION INOUT ;
    USE GROUND ;
    PORT
      LAYER M5 ;
        RECT  61.8 2.137 61.92 27.819 ;
        RECT  59.1 2.137 59.22 27.819 ;
        RECT  56.4 2.137 56.52 27.819 ;
        RECT  53.7 2.137 53.82 27.819 ;
        RECT  51 2.137 51.12 27.819 ;
        RECT  48.3 2.137 48.42 27.819 ;
        RECT  45.6 2.137 45.72 27.819 ;
        RECT  42.9 2.137 43.02 27.819 ;
        RECT  40.2 2.137 40.32 27.819 ;
        RECT  37.5 2.137 37.62 27.819 ;
        RECT  34.8 2.137 34.92 27.819 ;
        RECT  32.1 2.137 32.22 27.819 ;
        RECT  29.4 2.137 29.52 27.819 ;
        RECT  26.7 2.137 26.82 27.819 ;
        RECT  24 2.137 24.12 27.819 ;
        RECT  21.3 2.137 21.42 27.819 ;
        RECT  18.6 2.137 18.72 27.819 ;
        RECT  15.9 2.137 16.02 27.819 ;
        RECT  13.2 2.137 13.32 27.819 ;
        RECT  10.5 2.137 10.62 27.819 ;
        RECT  7.8 2.137 7.92 27.819 ;
        RECT  5.1 2.137 5.22 27.819 ;
        RECT  2.4 2.137 2.52 27.819 ;
    END
  END VSS
  OBS
    LAYER RVTN ;
     RECT  2.16 2.16 62.586 2.295 ;
     RECT  2.16 2.565 62.586 2.835 ;
     RECT  2.16 3.105 62.586 3.375 ;
     RECT  2.16 3.645 62.586 3.915 ;
     RECT  2.16 4.185 62.586 4.455 ;
     RECT  2.16 4.725 62.586 4.995 ;
     RECT  2.16 5.265 62.586 5.535 ;
     RECT  2.16 5.805 62.586 6.075 ;
     RECT  2.16 6.345 62.586 6.615 ;
     RECT  2.16 6.885 62.586 7.155 ;
     RECT  2.16 7.425 62.586 7.695 ;
     RECT  2.16 7.965 62.586 8.235 ;
     RECT  2.16 8.505 62.586 8.775 ;
     RECT  2.16 9.045 62.586 9.315 ;
     RECT  2.16 9.585 62.586 9.855 ;
     RECT  2.16 10.125 62.586 10.395 ;
     RECT  2.16 10.665 62.586 10.935 ;
     RECT  2.16 11.205 62.586 11.475 ;
     RECT  2.16 11.745 62.586 12.015 ;
     RECT  2.16 12.285 62.586 12.555 ;
     RECT  2.16 12.825 62.586 13.095 ;
     RECT  2.16 13.365 62.586 13.635 ;
     RECT  2.16 13.905 62.586 14.175 ;
     RECT  2.16 14.445 62.586 14.715 ;
     RECT  2.16 14.985 62.586 15.255 ;
     RECT  2.16 15.525 62.586 15.795 ;
     RECT  2.16 16.065 62.586 16.335 ;
     RECT  2.16 16.605 62.586 16.875 ;
     RECT  2.16 17.145 62.586 17.415 ;
     RECT  2.16 17.685 62.586 17.955 ;
     RECT  2.16 18.225 62.586 18.495 ;
     RECT  2.16 18.765 62.586 19.035 ;
     RECT  2.16 19.305 62.586 19.575 ;
     RECT  2.16 19.845 62.586 20.115 ;
     RECT  2.16 20.385 62.586 20.655 ;
     RECT  2.16 20.925 62.586 21.195 ;
     RECT  2.16 21.465 62.586 21.735 ;
     RECT  2.16 22.005 62.586 22.275 ;
     RECT  2.16 22.545 62.586 22.815 ;
     RECT  2.16 23.085 62.586 23.355 ;
     RECT  2.16 23.625 62.586 23.895 ;
     RECT  2.16 24.165 62.586 24.435 ;
     RECT  2.16 24.705 62.586 24.975 ;
     RECT  2.16 25.245 62.586 25.515 ;
     RECT  2.16 25.785 62.586 26.055 ;
     RECT  2.16 26.325 62.586 26.595 ;
     RECT  2.16 26.865 62.586 27.135 ;
     RECT  2.16 27.405 62.586 27.675 ;
    LAYER RVTP ;
     RECT  2.16 2.295 62.586 2.565 ;
     RECT  2.16 2.835 62.586 3.105 ;
     RECT  2.16 3.375 62.586 3.645 ;
     RECT  2.16 3.915 62.586 4.185 ;
     RECT  2.16 4.455 62.586 4.725 ;
     RECT  2.16 4.995 62.586 5.265 ;
     RECT  2.16 5.535 62.586 5.805 ;
     RECT  2.16 6.075 62.586 6.345 ;
     RECT  2.16 6.615 62.586 6.885 ;
     RECT  2.16 7.155 62.586 7.425 ;
     RECT  2.16 7.695 62.586 7.965 ;
     RECT  2.16 8.235 62.586 8.505 ;
     RECT  2.16 8.775 62.586 9.045 ;
     RECT  2.16 9.315 62.586 9.585 ;
     RECT  2.16 9.855 62.586 10.125 ;
     RECT  2.16 10.395 62.586 10.665 ;
     RECT  2.16 10.935 62.586 11.205 ;
     RECT  2.16 11.475 62.586 11.745 ;
     RECT  2.16 12.015 62.586 12.285 ;
     RECT  2.16 12.555 62.586 12.825 ;
     RECT  2.16 13.095 62.586 13.365 ;
     RECT  2.16 13.635 62.586 13.905 ;
     RECT  2.16 14.175 62.586 14.445 ;
     RECT  2.16 14.715 62.586 14.985 ;
     RECT  2.16 15.255 62.586 15.525 ;
     RECT  2.16 15.795 62.586 16.065 ;
     RECT  2.16 16.335 62.586 16.605 ;
     RECT  2.16 16.875 62.586 17.145 ;
     RECT  2.16 17.415 62.586 17.685 ;
     RECT  2.16 17.955 62.586 18.225 ;
     RECT  2.16 18.495 62.586 18.765 ;
     RECT  2.16 19.035 62.586 19.305 ;
     RECT  2.16 19.575 62.586 19.845 ;
     RECT  2.16 20.115 62.586 20.385 ;
     RECT  2.16 20.655 62.586 20.925 ;
     RECT  2.16 21.195 62.586 21.465 ;
     RECT  2.16 21.735 62.586 22.005 ;
     RECT  2.16 22.275 62.586 22.545 ;
     RECT  2.16 22.815 62.586 23.085 ;
     RECT  2.16 23.355 62.586 23.625 ;
     RECT  2.16 23.895 62.586 24.165 ;
     RECT  2.16 24.435 62.586 24.705 ;
     RECT  2.16 24.975 62.586 25.245 ;
     RECT  2.16 25.515 62.586 25.785 ;
     RECT  2.16 26.055 62.586 26.325 ;
     RECT  2.16 26.595 62.586 26.865 ;
     RECT  2.16 27.135 62.586 27.405 ;
     RECT  2.16 27.675 62.586 27.81 ;
    LAYER M1 ;
     RECT  2.16 2.151 62.586 27.819 ;
    LAYER M2 ;
     RECT  2.16 2.151 24.655 27.819 ;
     RECT  24.655 2.151 24.835 27.864 ;
     RECT  24.835 2.151 25.123 27.9 ;
     RECT  24.871 29.034 25.663 29.052 ;
     RECT  25.015 29.961 25.663 29.979 ;
     RECT  25.663 29.034 26.383 29.979 ;
     RECT  26.383 29.034 26.599 30.168 ;
     RECT  25.123 2.151 26.779 27.936 ;
     RECT  26.779 2.151 26.815 28.008 ;
     RECT  26.815 2.151 27.059 28.044 ;
     RECT  27.059 2.151 27.707 28.008 ;
     RECT  26.599 28.962 28.931 30.168 ;
     RECT  28.931 29.34 29.651 30.168 ;
     RECT  29.651 29.961 29.795 30.168 ;
     RECT  27.707 2.151 29.939 27.936 ;
     RECT  29.795 30.042 30.083 30.168 ;
     RECT  29.939 2.151 31.567 27.819 ;
     RECT  30.083 30.078 31.639 30.168 ;
     RECT  31.639 29.961 31.739 30.168 ;
     RECT  31.567 2.151 32.071 27.864 ;
     RECT  32.071 2.151 32.575 27.9 ;
     RECT  31.243 29.034 32.935 29.052 ;
     RECT  31.739 30.006 32.935 30.168 ;
     RECT  32.935 28.998 33.035 29.052 ;
     RECT  32.935 29.961 33.035 30.168 ;
     RECT  33.035 30.078 33.071 30.168 ;
     RECT  33.071 30.078 33.395 30.096 ;
     RECT  33.035 29.034 35.159 29.052 ;
     RECT  32.575 2.151 35.627 27.936 ;
     RECT  35.627 2.151 36.707 27.9 ;
     RECT  36.707 2.151 36.851 27.864 ;
     RECT  36.851 2.151 62.586 27.819 ;
     RECT  62.586 6.786 63.311 19.224 ;
     RECT  63.311 18.126 63.347 18.864 ;
     RECT  63.311 6.786 63.887 16.974 ;
     RECT  63.347 18.81 63.887 18.864 ;
     RECT  63.887 7.056 63.923 9.954 ;
     RECT  63.887 11.286 63.923 12.78 ;
     RECT  63.887 13.536 63.923 14.364 ;
     RECT  63.887 15.606 63.923 16.794 ;
     RECT  63.923 7.326 63.959 7.344 ;
     RECT  63.923 11.556 63.959 12.546 ;
     RECT  63.887 18.846 63.959 18.864 ;
     RECT  63.959 11.754 63.995 12.474 ;
     RECT  64.615 10.206 64.651 10.224 ;
     RECT  63.923 13.806 64.679 14.364 ;
     RECT  64.651 7.866 64.751 8.46 ;
     RECT  64.651 9.486 64.751 10.224 ;
     RECT  63.995 12.456 64.751 12.474 ;
     RECT  64.679 13.806 64.751 13.824 ;
     RECT  64.651 15.876 64.751 15.894 ;
     RECT  64.651 17.811 64.751 18.144 ;
    LAYER M3 ;
     RECT  2.415 2.143 2.505 2.413 ;
     RECT  5.115 2.143 5.205 2.413 ;
     RECT  7.815 2.143 7.905 2.413 ;
     RECT  10.515 2.143 10.605 2.413 ;
     RECT  13.215 2.143 13.305 2.413 ;
     RECT  15.915 2.143 16.005 2.413 ;
     RECT  18.615 2.143 18.705 2.413 ;
     RECT  21.315 2.143 21.405 2.413 ;
     RECT  24.015 2.143 24.105 2.413 ;
     RECT  26.715 2.143 26.805 2.413 ;
     RECT  29.415 2.143 29.505 2.413 ;
     RECT  32.115 2.143 32.205 2.413 ;
     RECT  34.815 2.143 34.905 2.413 ;
     RECT  37.515 2.143 37.605 2.413 ;
     RECT  40.215 2.143 40.305 2.413 ;
     RECT  42.915 2.143 43.005 2.413 ;
     RECT  45.615 2.143 45.705 2.413 ;
     RECT  48.315 2.143 48.405 2.413 ;
     RECT  51.015 2.143 51.105 2.413 ;
     RECT  53.715 2.143 53.805 2.413 ;
     RECT  56.415 2.143 56.505 2.413 ;
     RECT  59.115 2.143 59.205 2.413 ;
     RECT  61.815 2.143 61.905 2.413 ;
     RECT  29.415 2.413 29.697 6.817 ;
     RECT  63.864 6.781 63.882 7.051 ;
     RECT  29.376 6.817 29.697 7.087 ;
     RECT  61.815 2.413 62.097 7.243 ;
     RECT  62.82 7.195 62.838 7.243 ;
     RECT  29.376 7.087 30.366 7.339 ;
     RECT  63.864 7.051 63.954 7.349 ;
     RECT  61.815 7.243 62.838 7.373 ;
     RECT  29.376 7.339 30.69 7.387 ;
     RECT  32.115 2.413 32.397 7.387 ;
     RECT  29.376 7.387 32.397 7.501 ;
     RECT  61.815 7.373 62.73 7.661 ;
     RECT  64.656 7.819 64.674 7.861 ;
     RECT  28.872 7.501 32.397 7.889 ;
     RECT  30.78 7.889 32.397 7.915 ;
     RECT  30.78 7.915 32.814 8.005 ;
     RECT  34.815 2.413 35.097 8.239 ;
     RECT  63.864 7.349 63.918 8.275 ;
     RECT  30.78 8.005 33.246 8.311 ;
     RECT  30.78 8.311 33.498 8.437 ;
     RECT  34.704 8.239 35.097 8.437 ;
     RECT  64.656 7.861 64.746 8.465 ;
     RECT  64.728 8.465 64.746 8.477 ;
     RECT  61.815 7.661 62.694 8.501 ;
     RECT  28.872 7.889 30.006 8.743 ;
     RECT  30.78 8.437 35.097 8.743 ;
     RECT  37.515 2.413 37.797 8.779 ;
     RECT  38.88 8.683 38.898 8.779 ;
     RECT  45.615 2.413 45.897 8.779 ;
     RECT  46.872 8.683 46.89 8.779 ;
     RECT  53.715 2.413 53.997 8.779 ;
     RECT  54.828 8.683 54.846 8.779 ;
     RECT  38.772 8.779 38.898 8.813 ;
     RECT  46.764 8.779 46.89 8.813 ;
     RECT  53.715 8.779 54.846 8.813 ;
     RECT  37.515 8.779 37.854 9.005 ;
     RECT  28.872 8.743 35.097 9.077 ;
     RECT  63.828 8.275 63.918 9.163 ;
     RECT  28.872 9.077 34.038 9.239 ;
     RECT  38.772 8.813 38.79 9.247 ;
     RECT  61.815 8.501 62.154 9.247 ;
     RECT  61.56 9.247 62.154 9.293 ;
     RECT  38.736 9.247 38.79 9.419 ;
     RECT  64.656 9.451 64.674 9.481 ;
     RECT  63.288 9.163 63.918 9.509 ;
     RECT  63.36 9.509 63.918 9.545 ;
     RECT  38.772 9.419 38.79 9.677 ;
     RECT  45.615 8.779 45.954 9.677 ;
     RECT  46.764 8.813 46.782 9.677 ;
     RECT  53.715 8.813 54.738 9.677 ;
     RECT  61.815 9.293 62.154 9.677 ;
     RECT  28.08 7.699 28.098 9.931 ;
     RECT  28.872 9.239 33.93 9.931 ;
     RECT  63.864 9.545 63.918 10.061 ;
     RECT  64.656 9.481 64.746 10.201 ;
     RECT  64.62 10.201 64.746 10.229 ;
     RECT  64.62 10.229 64.674 10.253 ;
     RECT  28.08 9.931 33.93 10.319 ;
     RECT  28.08 10.319 33.75 10.363 ;
     RECT  63.864 10.061 63.882 10.399 ;
     RECT  26.715 2.413 26.997 10.471 ;
     RECT  27.828 10.363 33.75 10.471 ;
     RECT  63.792 10.399 63.882 10.541 ;
     RECT  61.815 9.677 62.097 10.651 ;
     RECT  61.815 10.651 62.766 10.829 ;
     RECT  34.776 9.077 35.097 10.867 ;
     RECT  34.704 10.867 35.097 10.967 ;
     RECT  61.815 10.829 62.694 10.967 ;
     RECT  63.828 10.541 63.882 11.083 ;
     RECT  63.828 11.083 63.918 11.213 ;
     RECT  38.772 11.227 38.79 11.405 ;
     RECT  46.764 11.227 46.782 11.405 ;
     RECT  54.72 11.227 54.738 11.405 ;
     RECT  63.864 11.213 63.918 11.551 ;
     RECT  64.656 10.253 64.674 11.551 ;
     RECT  26.715 10.471 33.75 12.361 ;
     RECT  34.815 10.967 35.097 12.361 ;
     RECT  63.864 11.551 64.674 12.451 ;
     RECT  63.864 12.451 64.746 12.509 ;
     RECT  63.864 12.509 64.674 12.551 ;
     RECT  34.74 12.361 35.097 12.757 ;
     RECT  63.864 12.551 63.918 12.793 ;
     RECT  63.828 12.793 63.918 12.845 ;
     RECT  34.704 12.757 35.097 12.857 ;
     RECT  61.815 10.967 62.097 12.907 ;
     RECT  26.028 12.361 33.75 13.027 ;
     RECT  38.772 12.859 38.79 13.037 ;
     RECT  46.764 12.859 46.782 13.037 ;
     RECT  54.72 12.859 54.738 13.037 ;
     RECT  25.92 13.027 33.75 13.441 ;
     RECT  25.92 13.441 33.786 13.531 ;
     RECT  61.815 12.907 62.73 13.613 ;
     RECT  60.948 13.291 60.966 13.631 ;
     RECT  63.864 12.845 63.918 13.771 ;
     RECT  64.656 12.551 64.674 13.771 ;
     RECT  63.864 13.771 64.674 13.801 ;
     RECT  63.864 13.801 64.746 13.829 ;
     RECT  25.92 13.531 34.038 13.837 ;
     RECT  34.776 12.857 35.097 13.837 ;
     RECT  64.656 13.829 64.746 13.853 ;
     RECT  60.408 13.819 60.426 13.865 ;
     RECT  25.92 13.837 35.097 13.945 ;
     RECT  63.864 13.829 63.918 13.945 ;
     RECT  25.92 13.945 35.226 13.981 ;
     RECT  63.828 13.945 63.918 14.155 ;
     RECT  63.288 14.155 63.918 14.171 ;
     RECT  25.92 13.981 35.514 14.251 ;
     RECT  61.815 13.613 62.097 14.347 ;
     RECT  25.92 14.251 36.054 14.369 ;
     RECT  64.656 13.853 64.674 14.369 ;
     RECT  59.115 2.413 59.397 14.377 ;
     RECT  58.716 14.377 59.397 14.635 ;
     RECT  63.288 14.171 63.882 14.731 ;
     RECT  61.815 14.347 62.19 14.827 ;
     RECT  63.252 14.731 63.882 14.827 ;
     RECT  2.415 2.413 2.697 14.881 ;
     RECT  2.415 14.881 2.826 14.981 ;
     RECT  38.664 14.881 38.682 14.989 ;
     RECT  38.664 14.989 38.754 15.017 ;
     RECT  61.815 14.827 63.882 15.017 ;
     RECT  2.415 14.981 2.697 15.019 ;
     RECT  58.68 14.635 59.397 15.019 ;
     RECT  58.608 15.019 59.397 15.059 ;
     RECT  63.252 15.017 63.882 15.089 ;
     RECT  10.515 2.413 10.797 15.151 ;
     RECT  36.72 15.061 36.738 15.179 ;
     RECT  63.288 15.089 63.882 15.211 ;
     RECT  2.34 15.019 2.697 15.215 ;
     RECT  15.915 2.413 16.197 15.457 ;
     RECT  25.92 14.369 35.982 15.457 ;
     RECT  61.815 15.017 62.118 15.773 ;
     RECT  61.815 15.773 62.097 15.835 ;
     RECT  64.728 15.835 64.746 15.871 ;
     RECT  64.656 15.871 64.746 15.899 ;
     RECT  64.656 15.899 64.674 15.917 ;
     RECT  25.92 15.457 36.702 15.961 ;
     RECT  37.515 9.005 37.797 15.961 ;
     RECT  38.7 15.017 38.754 15.961 ;
     RECT  63.288 15.211 63.918 15.979 ;
     RECT  63.252 15.979 63.918 16.025 ;
     RECT  25.92 15.961 37.797 16.097 ;
     RECT  25.92 16.097 35.874 16.259 ;
     RECT  37.224 16.097 37.797 16.259 ;
     RECT  38.628 15.961 38.754 16.363 ;
     RECT  38.592 16.363 38.754 16.375 ;
     RECT  38.592 16.375 38.79 16.403 ;
     RECT  61.524 15.835 62.097 16.403 ;
     RECT  55.296 16.339 55.314 16.589 ;
     RECT  63.828 16.025 63.918 16.747 ;
     RECT  38.772 16.403 38.79 16.771 ;
     RECT  63.288 16.747 63.918 16.799 ;
     RECT  45.615 9.677 45.897 16.843 ;
     RECT  53.715 9.677 53.997 16.843 ;
     RECT  61.815 16.403 62.097 16.843 ;
     RECT  37.515 16.259 37.797 16.939 ;
     RECT  45.615 16.843 45.99 16.973 ;
     RECT  46.764 16.843 46.782 16.973 ;
     RECT  53.715 16.843 54.738 16.973 ;
     RECT  63.288 16.799 63.882 16.979 ;
     RECT  37.515 16.939 37.89 17.077 ;
     RECT  61.815 16.843 62.19 17.131 ;
     RECT  63.288 16.979 63.306 17.131 ;
     RECT  36.936 17.077 37.89 17.311 ;
     RECT  38.772 16.771 38.826 17.311 ;
     RECT  61.815 17.131 63.306 17.419 ;
     RECT  36.936 17.311 38.826 17.447 ;
     RECT  36.936 17.447 37.797 17.491 ;
     RECT  59.115 15.059 59.397 17.611 ;
     RECT  58.68 17.611 59.397 17.753 ;
     RECT  61.524 17.419 63.306 17.789 ;
     RECT  64.656 17.8 64.674 17.806 ;
     RECT  25.92 16.259 35.838 17.851 ;
     RECT  36.576 17.491 37.797 17.851 ;
     RECT  61.815 17.789 63.306 17.899 ;
     RECT  46.764 17.851 46.782 17.981 ;
     RECT  54.72 17.851 54.738 17.981 ;
     RECT  56.415 2.413 56.697 17.995 ;
     RECT  64.656 17.806 64.746 18.149 ;
     RECT  64.728 18.149 64.746 18.173 ;
     RECT  25.92 17.851 37.797 18.265 ;
     RECT  55.836 17.995 56.697 18.293 ;
     RECT  25.92 18.265 37.926 18.301 ;
     RECT  38.772 17.447 38.826 18.301 ;
     RECT  59.115 17.753 59.397 18.301 ;
     RECT  59.115 18.301 59.85 18.461 ;
     RECT  61.815 17.899 63.342 18.563 ;
     RECT  25.92 18.301 38.826 18.571 ;
     RECT  63.288 18.563 63.342 18.571 ;
     RECT  59.115 18.461 59.778 18.599 ;
     RECT  25.92 18.571 38.898 18.761 ;
     RECT  63.288 18.571 63.882 18.763 ;
     RECT  60.696 18.661 60.714 18.797 ;
     RECT  61.815 18.563 62.19 18.797 ;
     RECT  63.288 18.763 63.954 18.869 ;
     RECT  25.92 18.761 38.754 19.139 ;
     RECT  63.288 18.869 63.306 19.229 ;
     RECT  61.815 18.797 62.097 19.345 ;
     RECT  25.92 19.139 38.538 19.499 ;
     RECT  61.74 19.345 62.097 19.499 ;
     RECT  45.615 16.973 45.897 19.579 ;
     RECT  59.115 18.599 59.397 19.615 ;
     RECT  60.876 19.345 60.894 19.643 ;
     RECT  59.115 19.615 60.102 19.661 ;
     RECT  15.804 15.457 16.197 21.397 ;
     RECT  15.804 21.397 16.83 21.437 ;
     RECT  15.804 21.437 16.614 21.499 ;
     RECT  15.696 21.499 16.614 21.569 ;
     RECT  15.804 21.569 16.614 21.659 ;
     RECT  10.515 15.151 11.106 21.731 ;
     RECT  15.804 21.659 16.506 21.839 ;
     RECT  15.804 21.839 16.434 22.205 ;
     RECT  21.315 2.413 21.597 22.727 ;
     RECT  21.315 22.727 22.086 22.981 ;
     RECT  21.315 22.981 22.806 22.987 ;
     RECT  24.015 2.413 24.297 22.987 ;
     RECT  21.315 22.987 24.297 23.021 ;
     RECT  22.644 23.021 24.297 23.117 ;
     RECT  25.92 19.499 37.797 23.227 ;
     RECT  21.315 23.021 21.906 23.279 ;
     RECT  24.015 23.117 24.297 23.323 ;
     RECT  25.236 23.227 37.797 23.323 ;
     RECT  24.015 23.323 37.797 23.36 ;
     RECT  25.236 23.36 37.797 23.453 ;
     RECT  15.804 22.205 16.197 23.459 ;
     RECT  45.615 19.579 46.458 23.791 ;
     RECT  22.644 23.117 22.878 23.837 ;
     RECT  48.315 2.413 48.597 23.851 ;
     RECT  40.215 2.413 40.497 23.899 ;
     RECT  45.615 23.791 46.71 23.899 ;
     RECT  47.592 23.851 48.597 23.899 ;
     RECT  42.915 2.413 43.197 23.971 ;
     RECT  22.86 23.837 22.878 23.981 ;
     RECT  21.315 23.279 21.654 24.089 ;
     RECT  45.615 23.899 48.597 24.089 ;
     RECT  45.615 24.089 46.926 24.125 ;
     RECT  38.52 19.499 38.538 24.133 ;
     RECT  46.908 24.125 46.926 24.173 ;
     RECT  42.768 23.971 43.197 24.233 ;
     RECT  38.52 24.133 38.754 24.413 ;
     RECT  40.215 23.899 41.022 24.475 ;
     RECT  25.92 23.453 37.797 25.015 ;
     RECT  38.52 24.413 38.538 25.015 ;
     RECT  25.92 25.015 38.538 25.147 ;
     RECT  25.92 25.147 38.79 25.169 ;
     RECT  25.92 25.169 37.89 25.277 ;
     RECT  38.772 25.169 38.79 25.277 ;
     RECT  40.215 24.475 41.454 25.619 ;
     RECT  25.092 25.675 25.11 25.745 ;
     RECT  41.436 25.619 41.454 25.757 ;
     RECT  25.92 25.277 37.797 25.789 ;
     RECT  25.452 25.789 37.797 26.527 ;
     RECT  24.015 23.36 24.297 26.905 ;
     RECT  25.092 26.527 37.797 26.905 ;
     RECT  2.415 15.215 2.697 27.557 ;
     RECT  5.115 2.413 5.397 27.557 ;
     RECT  7.815 2.413 8.097 27.557 ;
     RECT  10.515 21.731 10.797 27.557 ;
     RECT  13.215 2.413 13.497 27.557 ;
     RECT  15.915 23.459 16.197 27.557 ;
     RECT  18.615 2.413 18.897 27.557 ;
     RECT  21.315 24.089 21.597 27.557 ;
     RECT  24.015 26.905 37.797 27.557 ;
     RECT  40.215 25.619 40.497 27.557 ;
     RECT  42.915 24.233 43.197 27.557 ;
     RECT  45.615 24.125 45.897 27.557 ;
     RECT  48.315 24.089 48.597 27.557 ;
     RECT  51.015 2.413 51.297 27.557 ;
     RECT  53.715 16.973 53.997 27.557 ;
     RECT  56.415 18.293 56.697 27.557 ;
     RECT  59.115 19.661 59.397 27.557 ;
     RECT  61.815 19.499 62.097 27.557 ;
     RECT  2.607 27.557 2.697 27.827 ;
     RECT  5.307 27.557 5.397 27.827 ;
     RECT  8.007 27.557 8.097 27.827 ;
     RECT  10.707 27.557 10.797 27.827 ;
     RECT  13.407 27.557 13.497 27.827 ;
     RECT  16.107 27.557 16.197 27.827 ;
     RECT  18.807 27.557 18.897 27.827 ;
     RECT  21.507 27.557 21.597 27.827 ;
     RECT  24.207 27.557 37.797 27.827 ;
     RECT  40.407 27.557 40.497 27.827 ;
     RECT  43.107 27.557 43.197 27.827 ;
     RECT  45.807 27.557 45.897 27.827 ;
     RECT  48.507 27.557 48.597 27.827 ;
     RECT  51.207 27.557 51.297 27.827 ;
     RECT  53.907 27.557 53.997 27.827 ;
     RECT  56.607 27.557 56.697 27.827 ;
     RECT  59.307 27.557 59.397 27.827 ;
     RECT  62.007 27.557 62.097 27.827 ;
     RECT  24.66 27.827 36.99 27.869 ;
     RECT  24.804 27.869 36.99 28.205 ;
     RECT  24.876 28.205 36.99 28.397 ;
     RECT  24.876 28.397 35.154 28.445 ;
     RECT  24.876 28.445 33.93 28.493 ;
     RECT  24.876 28.493 33.39 29.057 ;
     RECT  35.136 28.445 35.154 29.057 ;
     RECT  25.02 29.057 33.39 29.633 ;
     RECT  25.812 29.633 33.39 29.939 ;
     RECT  25.02 29.633 25.038 29.984 ;
     RECT  25.992 29.939 33.39 30.077 ;
     RECT  36 28.397 36.99 30.077 ;
     RECT  26.244 30.077 33.39 30.101 ;
     RECT  36 30.077 36.018 30.125 ;
     RECT  26.244 30.101 33.282 30.173 ;
     RECT  36.972 30.077 36.99 30.173 ;
     RECT  26.244 30.173 33.102 30.204 ;
    LAYER M4 ;
     RECT  0.06 14.832 0.227 15.048 ;
     RECT  0.227 14.928 2.408 15.048 ;
     RECT  0.181 23.616 2.408 23.64 ;
     RECT  2.408 2.148 2.512 27.552 ;
     RECT  2.512 2.418 2.6 27.552 ;
     RECT  2.6 2.418 2.704 27.822 ;
     RECT  2.704 14.928 5.108 14.952 ;
     RECT  2.704 23.616 5.108 23.64 ;
     RECT  5.108 2.148 5.212 27.552 ;
     RECT  5.212 2.418 5.3 27.552 ;
     RECT  5.3 2.418 5.404 27.822 ;
     RECT  5.404 14.928 7.808 14.952 ;
     RECT  5.404 23.616 7.808 23.64 ;
     RECT  7.808 2.148 7.912 27.552 ;
     RECT  7.912 2.418 8 27.552 ;
     RECT  8 2.418 8.104 27.822 ;
     RECT  8.104 14.928 10.508 14.952 ;
     RECT  8.104 23.616 10.508 23.64 ;
     RECT  10.508 2.148 10.612 27.552 ;
     RECT  10.612 2.418 10.7 27.552 ;
     RECT  10.7 2.418 10.804 27.822 ;
     RECT  10.804 14.928 13.208 14.952 ;
     RECT  10.804 23.616 13.208 23.64 ;
     RECT  13.208 2.148 13.312 27.552 ;
     RECT  13.312 2.418 13.4 27.552 ;
     RECT  13.4 2.418 13.504 27.822 ;
     RECT  13.504 14.928 15.908 14.952 ;
     RECT  15.685 21.504 15.908 21.528 ;
     RECT  13.504 23.616 15.908 23.64 ;
     RECT  15.908 2.148 16.012 27.552 ;
     RECT  16.012 2.418 16.1 27.552 ;
     RECT  16.1 2.418 16.204 27.822 ;
     RECT  16.204 21.408 16.547 22.2 ;
     RECT  16.547 21.408 16.625 21.528 ;
     RECT  16.204 14.928 18.608 14.952 ;
     RECT  16.625 21.408 18.608 21.432 ;
     RECT  16.204 23.328 18.608 23.64 ;
     RECT  18.608 2.148 18.712 27.552 ;
     RECT  18.712 2.418 18.8 27.552 ;
     RECT  18.8 2.418 18.904 27.822 ;
     RECT  18.904 23.328 21.157 23.64 ;
     RECT  18.904 14.928 21.308 14.952 ;
     RECT  18.904 21.408 21.308 21.432 ;
     RECT  21.157 23.136 21.308 23.64 ;
     RECT  21.308 2.148 21.412 27.552 ;
     RECT  21.412 2.418 21.5 27.552 ;
     RECT  21.5 2.418 21.604 27.822 ;
     RECT  21.604 14.928 22.115 14.952 ;
     RECT  21.604 22.752 22.115 24.216 ;
     RECT  22.115 22.992 24.008 24.216 ;
     RECT  24.008 2.148 24.112 27.552 ;
     RECT  24.112 2.418 24.2 27.552 ;
     RECT  24.2 2.418 24.304 27.822 ;
     RECT  24.304 27.312 24.793 27.822 ;
     RECT  24.304 23.088 25.139 25.704 ;
     RECT  25.139 23.136 25.165 25.704 ;
     RECT  24.793 27.312 25.693 28.2 ;
     RECT  25.693 26.256 26.197 28.2 ;
     RECT  25.165 23.136 26.449 24.936 ;
     RECT  26.197 26.256 26.449 28.488 ;
     RECT  26.449 23.136 26.708 28.488 ;
     RECT  26.708 2.148 26.812 28.488 ;
     RECT  26.812 2.418 27.004 28.488 ;
     RECT  27.004 23.04 27.349 28.488 ;
     RECT  27.349 23.04 27.821 28.536 ;
     RECT  25.981 30.048 28.001 30.072 ;
     RECT  27.821 23.04 28.213 25.08 ;
     RECT  28.069 30.144 28.289 30.168 ;
     RECT  28.213 22.176 28.325 25.08 ;
     RECT  28.681 10.176 28.933 10.2 ;
     RECT  28.325 22.56 29.077 25.08 ;
     RECT  27.821 26.112 29.077 28.536 ;
     RECT  28.933 10.128 29.408 10.2 ;
     RECT  29.077 22.56 29.408 28.536 ;
     RECT  29.408 2.148 29.512 28.536 ;
     RECT  29.221 30.096 29.555 30.12 ;
     RECT  29.512 2.418 29.704 28.536 ;
     RECT  29.704 21.888 29.843 28.536 ;
     RECT  29.701 30.048 30.083 30.072 ;
     RECT  29.843 26.496 30.377 28.536 ;
     RECT  29.843 21.888 30.805 25.512 ;
     RECT  30.377 26.496 30.805 28.488 ;
     RECT  29.704 10.128 30.809 11.4 ;
     RECT  29.704 12.48 30.845 13.032 ;
     RECT  30.757 29.904 30.877 30.024 ;
     RECT  30.805 21.888 31.043 28.488 ;
     RECT  31.043 26.736 31.058 28.488 ;
     RECT  30.877 29.76 31.091 30.024 ;
     RECT  31.043 21.888 31.148 25.704 ;
     RECT  31.091 29.856 31.187 30.024 ;
     RECT  31.187 29.952 31.235 30.024 ;
     RECT  29.704 7.344 31.381 7.368 ;
     RECT  31.381 7.344 31.417 7.416 ;
     RECT  31.148 21.408 31.861 25.704 ;
     RECT  31.417 7.344 32.029 7.656 ;
     RECT  31.861 21.312 32.065 25.704 ;
     RECT  31.058 26.784 32.065 28.488 ;
     RECT  32.029 7.344 32.108 7.752 ;
     RECT  31.093 9.072 32.108 9.096 ;
     RECT  30.809 10.128 32.108 11.256 ;
     RECT  30.845 12.48 32.108 12.888 ;
     RECT  32.065 21.312 32.108 28.488 ;
     RECT  31.235 30 32.209 30.024 ;
     RECT  32.108 2.148 32.212 28.488 ;
     RECT  32.209 30 32.281 30.072 ;
     RECT  32.281 30 32.389 30.12 ;
     RECT  32.212 2.418 32.404 28.488 ;
     RECT  32.404 21.792 32.897 28.488 ;
     RECT  32.897 22.08 33.185 28.488 ;
     RECT  33.185 22.08 33.251 23.016 ;
     RECT  32.389 29.952 33.253 30.12 ;
     RECT  33.251 22.08 33.293 22.104 ;
     RECT  33.253 29.952 33.293 30.168 ;
     RECT  32.404 7.344 33.541 9 ;
     RECT  32.404 10.128 33.541 11.256 ;
     RECT  33.185 24 33.941 28.488 ;
     RECT  33.941 24 34.481 28.44 ;
     RECT  33.541 7.344 34.808 11.256 ;
     RECT  32.404 12.48 34.808 12.888 ;
     RECT  33.649 16.656 34.808 16.68 ;
     RECT  34.481 24 34.808 28.392 ;
     RECT  34.808 2.148 34.912 28.392 ;
     RECT  34.912 2.418 35.104 28.392 ;
     RECT  35.104 15.264 35.381 15.288 ;
     RECT  35.104 24.096 35.669 28.392 ;
     RECT  35.669 24.096 35.993 28.248 ;
     RECT  35.993 28.176 36.209 28.248 ;
     RECT  33.293 30.048 36.461 30.168 ;
     RECT  36.209 28.176 36.893 28.2 ;
     RECT  36.461 30.144 37.001 30.168 ;
     RECT  35.104 16.656 37.069 17.112 ;
     RECT  37.069 16.656 37.105 17.64 ;
     RECT  35.104 7.344 37.508 11.256 ;
     RECT  35.104 12.48 37.508 12.888 ;
     RECT  36.457 15.504 37.508 15.528 ;
     RECT  37.105 16.656 37.508 17.976 ;
     RECT  35.104 19.056 37.508 19.08 ;
     RECT  35.993 24.096 37.508 26.904 ;
     RECT  37.508 2.148 37.612 27.822 ;
     RECT  37.612 2.418 37.804 27.822 ;
     RECT  37.804 15.504 38.405 19.08 ;
     RECT  38.405 15.504 38.765 17.976 ;
     RECT  37.804 7.344 38.801 11.4 ;
     RECT  37.804 12.48 38.801 13.032 ;
     RECT  38.765 16.656 38.801 17.976 ;
     RECT  38.801 17.856 38.837 17.976 ;
     RECT  38.801 7.344 40.208 11.256 ;
     RECT  38.801 12.48 40.208 12.888 ;
     RECT  38.765 15.504 40.208 15.528 ;
     RECT  38.801 16.656 40.208 16.872 ;
     RECT  38.837 17.952 40.208 17.976 ;
     RECT  38.405 18.96 40.208 19.08 ;
     RECT  37.804 24.144 40.208 25.752 ;
     RECT  40.208 2.148 40.312 27.552 ;
     RECT  40.312 2.418 40.4 27.552 ;
     RECT  40.4 2.418 40.504 27.822 ;
     RECT  40.504 23.904 41.141 25.752 ;
     RECT  41.141 25.248 41.465 25.752 ;
     RECT  40.504 18.96 41.893 19.08 ;
     RECT  41.141 23.904 41.939 24.264 ;
     RECT  40.504 7.344 42.908 11.256 ;
     RECT  40.504 12.48 42.908 12.888 ;
     RECT  40.504 15.504 42.908 15.528 ;
     RECT  40.504 16.656 42.908 16.872 ;
     RECT  40.504 17.952 42.908 17.976 ;
     RECT  41.893 18.96 42.908 19.656 ;
     RECT  41.939 23.904 42.908 24.168 ;
     RECT  42.908 2.148 43.012 27.552 ;
     RECT  43.012 2.418 43.1 27.552 ;
     RECT  43.1 2.418 43.204 27.822 ;
     RECT  43.204 7.344 45.608 11.256 ;
     RECT  43.204 12.48 45.608 12.888 ;
     RECT  43.204 15.504 45.608 15.528 ;
     RECT  43.204 16.656 45.608 16.872 ;
     RECT  43.204 17.952 45.608 17.976 ;
     RECT  43.204 18.96 45.608 19.656 ;
     RECT  43.204 23.904 45.608 24.168 ;
     RECT  45.608 2.148 45.712 27.552 ;
     RECT  45.712 2.418 45.8 27.552 ;
     RECT  45.8 2.418 45.904 27.822 ;
     RECT  45.904 7.344 46.793 11.4 ;
     RECT  45.904 12.48 46.793 13.032 ;
     RECT  45.904 16.656 46.793 17.976 ;
     RECT  45.904 23.856 46.937 24.168 ;
     RECT  46.937 23.856 47.009 23.928 ;
     RECT  46.793 7.344 48.308 11.256 ;
     RECT  46.793 12.48 48.308 12.888 ;
     RECT  45.904 15.504 48.308 15.528 ;
     RECT  46.793 16.656 48.308 16.872 ;
     RECT  46.793 17.952 48.308 17.976 ;
     RECT  45.904 18.96 48.308 19.656 ;
     RECT  47.009 23.856 48.308 23.88 ;
     RECT  48.308 2.148 48.412 27.552 ;
     RECT  48.412 2.418 48.5 27.552 ;
     RECT  48.5 2.418 48.604 27.822 ;
     RECT  48.604 7.344 51.008 11.256 ;
     RECT  48.604 12.48 51.008 12.888 ;
     RECT  48.604 15.504 51.008 15.528 ;
     RECT  48.604 16.656 51.008 16.872 ;
     RECT  48.604 17.952 51.008 17.976 ;
     RECT  48.604 18.96 51.008 19.656 ;
     RECT  51.008 2.148 51.112 27.552 ;
     RECT  51.112 2.418 51.2 27.552 ;
     RECT  51.2 2.418 51.304 27.822 ;
     RECT  51.304 7.344 53.708 11.256 ;
     RECT  51.304 12.48 53.708 12.888 ;
     RECT  51.304 15.504 53.708 15.528 ;
     RECT  51.304 16.656 53.708 16.872 ;
     RECT  51.304 17.952 53.708 17.976 ;
     RECT  51.304 18.96 53.708 19.656 ;
     RECT  53.708 2.148 53.812 27.552 ;
     RECT  53.812 2.418 53.9 27.552 ;
     RECT  53.9 2.418 54.004 27.822 ;
     RECT  54.004 7.344 54.749 11.4 ;
     RECT  54.004 12.48 54.749 13.032 ;
     RECT  54.004 16.656 54.749 17.976 ;
     RECT  54.749 16.656 55.285 16.872 ;
     RECT  54.749 17.952 55.825 17.976 ;
     RECT  54.004 18.96 55.825 19.656 ;
     RECT  54.749 7.344 56.408 11.256 ;
     RECT  54.749 12.48 56.408 12.888 ;
     RECT  54.004 15.504 56.408 15.528 ;
     RECT  55.285 16.56 56.408 16.872 ;
     RECT  55.825 17.952 56.408 19.656 ;
     RECT  56.408 2.148 56.512 27.552 ;
     RECT  56.512 2.418 56.6 27.552 ;
     RECT  56.6 2.418 56.704 27.822 ;
     RECT  56.704 15.504 58.597 15.528 ;
     RECT  58.597 15.024 58.669 15.528 ;
     RECT  56.704 16.56 58.669 16.872 ;
     RECT  56.704 17.952 58.669 19.656 ;
     RECT  56.704 7.344 59.108 11.256 ;
     RECT  56.704 12.48 59.108 12.888 ;
     RECT  58.669 14.64 59.108 15.528 ;
     RECT  58.669 16.56 59.108 19.656 ;
     RECT  59.108 2.148 59.212 27.552 ;
     RECT  59.212 2.418 59.3 27.552 ;
     RECT  59.3 2.418 59.404 27.822 ;
     RECT  59.404 16.56 60.113 19.656 ;
     RECT  59.404 12.48 60.397 12.888 ;
     RECT  59.404 14.64 60.397 15.528 ;
     RECT  60.397 12.48 61.513 15.528 ;
     RECT  60.113 16.56 61.513 19.08 ;
     RECT  59.404 7.344 61.808 11.256 ;
     RECT  61.513 12.48 61.808 19.08 ;
     RECT  61.808 2.148 61.912 27.552 ;
     RECT  61.912 2.418 62 27.552 ;
     RECT  62 2.418 62.104 27.822 ;
     RECT  62.104 7.2 62.849 11.4 ;
     RECT  62.104 12.48 63.277 19.08 ;
     RECT  62.849 7.248 63.853 11.4 ;
     RECT  63.277 12.48 63.853 19.176 ;
     RECT  63.853 6.864 64.716 19.176 ;
     RECT  64.716 7.872 64.757 8.472 ;
     RECT  64.716 9.504 64.757 10.2 ;
     RECT  64.716 12.48 64.757 12.504 ;
     RECT  64.716 13.824 64.757 13.848 ;
     RECT  64.716 15.84 64.757 15.864 ;
     RECT  64.716 17.856 64.757 18.168 ;
    LAYER M5 ;
     RECT  2.4 2.137 2.52 2.151 ;
     RECT  5.1 2.137 5.22 2.151 ;
     RECT  7.8 2.137 7.92 2.151 ;
     RECT  10.5 2.137 10.62 2.151 ;
     RECT  13.2 2.137 13.32 2.151 ;
     RECT  15.9 2.137 16.02 2.151 ;
     RECT  18.6 2.137 18.72 2.151 ;
     RECT  21.3 2.137 21.42 2.151 ;
     RECT  24 2.137 24.12 2.151 ;
     RECT  26.7 2.137 26.82 2.151 ;
     RECT  29.4 2.137 29.52 2.151 ;
     RECT  32.1 2.137 32.22 2.151 ;
     RECT  34.8 2.137 34.92 2.151 ;
     RECT  37.5 2.137 37.62 2.151 ;
     RECT  40.2 2.137 40.32 2.151 ;
     RECT  42.9 2.137 43.02 2.151 ;
     RECT  45.6 2.137 45.72 2.151 ;
     RECT  48.3 2.137 48.42 2.151 ;
     RECT  51 2.137 51.12 2.151 ;
     RECT  53.7 2.137 53.82 2.151 ;
     RECT  56.4 2.137 56.52 2.151 ;
     RECT  59.1 2.137 59.22 2.151 ;
     RECT  61.8 2.137 61.92 2.151 ;
     RECT  61.8 2.151 62.112 7.189 ;
     RECT  61.8 7.189 62.76 7.427 ;
     RECT  21.3 2.151 21.612 14.917 ;
     RECT  31.104 9.061 31.128 21.301 ;
     RECT  32.1 2.151 32.412 21.301 ;
     RECT  21.3 14.917 22.104 21.397 ;
     RECT  31.104 21.301 32.412 21.877 ;
     RECT  30.912 21.877 32.412 22.069 ;
     RECT  15.9 2.151 16.212 22.165 ;
     RECT  29.4 2.151 29.712 22.741 ;
     RECT  30.912 22.069 33.24 22.741 ;
     RECT  21.168 21.397 22.104 22.787 ;
     RECT  29.4 22.741 33.24 23.027 ;
     RECT  24 2.151 24.312 23.077 ;
     RECT  21.168 22.787 21.612 23.171 ;
     RECT  15.9 22.165 16.536 23.363 ;
     RECT  29.4 23.027 33.096 23.365 ;
     RECT  0.192 14.821 0.216 23.651 ;
     RECT  26.7 2.151 27.012 23.797 ;
     RECT  28.224 22.165 28.248 23.797 ;
     RECT  26.7 23.797 28.248 23.941 ;
     RECT  22.848 23.845 22.872 23.987 ;
     RECT  41.904 19.621 41.928 24.275 ;
     RECT  37.5 2.151 37.812 24.421 ;
     RECT  26.592 23.941 28.248 25.045 ;
     RECT  29.232 23.365 33.096 25.045 ;
     RECT  34.8 2.151 35.112 25.045 ;
     RECT  36.576 24.421 37.812 25.045 ;
     RECT  34.8 25.045 37.812 25.187 ;
     RECT  26.592 25.045 33.672 25.331 ;
     RECT  26.7 25.331 33.672 25.621 ;
     RECT  34.8 25.187 35.784 25.621 ;
     RECT  24 23.077 25.128 25.715 ;
     RECT  26.7 25.621 35.784 25.715 ;
     RECT  26.7 25.715 27.384 25.763 ;
     RECT  28.416 25.715 33.096 26.483 ;
     RECT  34.224 25.715 35.784 26.531 ;
     RECT  34.224 26.531 35.112 26.867 ;
     RECT  26.7 25.763 27.144 27.395 ;
     RECT  29.088 26.483 33.096 27.395 ;
     RECT  34.608 26.867 35.112 27.395 ;
     RECT  29.088 27.395 32.52 27.635 ;
     RECT  2.4 2.151 2.712 27.819 ;
     RECT  5.1 2.151 5.412 27.819 ;
     RECT  7.8 2.151 8.112 27.819 ;
     RECT  10.5 2.151 10.812 27.819 ;
     RECT  13.2 2.151 13.512 27.819 ;
     RECT  15.9 23.363 16.212 27.819 ;
     RECT  18.6 2.151 18.912 27.819 ;
     RECT  21.3 23.171 21.612 27.819 ;
     RECT  24 25.715 24.312 27.819 ;
     RECT  26.7 27.395 27.012 27.819 ;
     RECT  34.8 27.395 35.112 27.819 ;
     RECT  37.5 25.187 37.812 27.819 ;
     RECT  40.2 2.151 40.512 27.819 ;
     RECT  42.9 2.151 43.212 27.819 ;
     RECT  45.6 2.151 45.912 27.819 ;
     RECT  48.3 2.151 48.612 27.819 ;
     RECT  51 2.151 51.312 27.819 ;
     RECT  53.7 2.151 54.012 27.819 ;
     RECT  56.4 2.151 56.712 27.819 ;
     RECT  59.1 2.151 59.412 27.819 ;
     RECT  61.8 7.427 62.112 27.819 ;
     RECT  2.592 27.819 2.712 27.833 ;
     RECT  5.292 27.819 5.412 27.833 ;
     RECT  7.992 27.819 8.112 27.833 ;
     RECT  10.692 27.819 10.812 27.833 ;
     RECT  13.392 27.819 13.512 27.833 ;
     RECT  16.092 27.819 16.212 27.833 ;
     RECT  18.792 27.819 18.912 27.833 ;
     RECT  21.492 27.819 21.612 27.833 ;
     RECT  24.192 27.819 24.312 27.833 ;
     RECT  26.892 27.819 27.012 27.833 ;
     RECT  34.992 27.819 35.112 27.833 ;
     RECT  37.692 27.819 37.812 27.833 ;
     RECT  40.392 27.819 40.512 27.833 ;
     RECT  43.092 27.819 43.212 27.833 ;
     RECT  45.792 27.819 45.912 27.833 ;
     RECT  48.492 27.819 48.612 27.833 ;
     RECT  51.192 27.819 51.312 27.833 ;
     RECT  53.892 27.819 54.012 27.833 ;
     RECT  56.592 27.819 56.712 27.833 ;
     RECT  59.292 27.819 59.412 27.833 ;
     RECT  61.992 27.819 62.112 27.833 ;
     RECT  29.232 27.635 32.52 29.989 ;
     RECT  29.232 29.989 33.048 30.131 ;
     RECT  29.52 30.131 32.52 30.16 ;
  END
END qfd_rlyh0_128_NE_65x30
END LIBRARY
